VERSION 5.8 ;
BUSBITCHARS "[]" ;
DIVIDERCHAR "/" ;
 
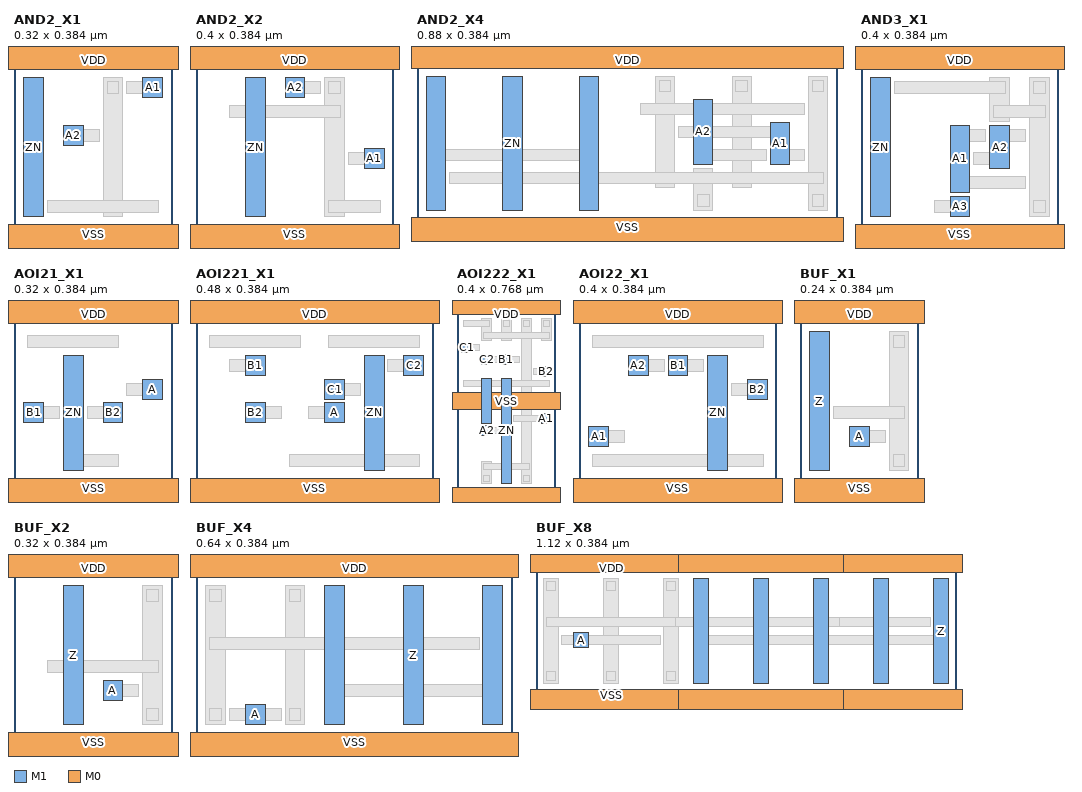
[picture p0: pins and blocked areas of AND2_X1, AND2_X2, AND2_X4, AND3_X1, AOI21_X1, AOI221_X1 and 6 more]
MACRO AND2_X1
  CLASS CORE ;
  FOREIGN AND2_X1 0 0 ;
  SIZE 0.32 BY 0.384 ;
  ORIGIN 0.0 0.0 ;
  SYMMETRY X Y ;
  PIN A1
    DIRECTION INPUT ;
    USE SIGNAL ;
    ANTENNAGATEAREA 0.00320 ;
    PORT
      LAYER M1 ;
        RECT 0.26 0.292 0.3 0.332 ;
    END
  END A1
  PIN A2
    DIRECTION INPUT ;
    USE SIGNAL ;
    ANTENNAGATEAREA 0.00320 ;
    PORT
      LAYER M1 ;
        RECT 0.1 0.196 0.14 0.236 ;
    END
  END A2
  PIN ZN
    DIRECTION OUTPUT ;
    USE SIGNAL ;
    ANTENNADIFFAREA 0.0096 ;
    PORT
      LAYER M1 ;
        RECT 0.02 0.052 0.06 0.332 ;
    END
  END ZN
  PIN VDD
    DIRECTION INOUT ;
    USE POWER ;
    PORT
      LAYER M0 ;
        RECT -0.02 0.348 0.34 0.42 ;
    END
  END VDD
  PIN VSS
    DIRECTION INOUT ;
    USE GROUND ;
    PORT
      LAYER M0 ;
        RECT -0.02 -0.036 0.34 0.036 ;
    END
  END VSS
  OBS
    LAYER M1 ;
      RECT 0.18 0.052 0.22 0.332 ;
    LAYER M0 ;
      RECT 0.068 0.06 0.292 0.084 ;
      RECT 0.188 0.3 0.212 0.324 ;
      RECT 0.228 0.3 0.292 0.324 ;
      RECT 0.108 0.204 0.172 0.228 ;
      RECT 0.028 0.06 0.052 0.084 ;
      RECT 0.028 0.3 0.052 0.324 ;
  END
END AND2_X1

MACRO AND2_X2
  CLASS CORE ;
  FOREIGN AND2_X2 0 0 ;
  SIZE 0.4 BY 0.384 ;
  ORIGIN 0.0 0.0 ;
  SYMMETRY X Y ;
  PIN A1
    DIRECTION INPUT ;
    USE SIGNAL ;
    ANTENNAGATEAREA 0.00320 ;
    PORT
      LAYER M1 ;
        RECT 0.34 0.148 0.38 0.188 ;
    END
  END A1
  PIN A2
    DIRECTION INPUT ;
    USE SIGNAL ;
    ANTENNAGATEAREA 0.00320 ;
    PORT
      LAYER M1 ;
        RECT 0.18 0.292 0.22 0.332 ;
    END
  END A2
  PIN ZN
    DIRECTION OUTPUT ;
    USE SIGNAL ;
    ANTENNADIFFAREA 0.0096 ;
    PORT
      LAYER M1 ;
        RECT 0.1 0.052 0.14 0.332 ;
    END
  END ZN
  PIN VDD
    DIRECTION INOUT ;
    USE POWER ;
    PORT
      LAYER M0 ;
        RECT -0.02 0.348 0.42 0.42 ;
    END
  END VDD
  PIN VSS
    DIRECTION INOUT ;
    USE GROUND ;
    PORT
      LAYER M0 ;
        RECT -0.02 -0.036 0.42 0.036 ;
    END
  END VSS
  OBS
    LAYER M1 ;
      RECT 0.26 0.052 0.3 0.332 ;
    LAYER M0 ;
      RECT 0.068 0.252 0.292 0.276 ;
      RECT 0.268 0.06 0.372 0.084 ;
      RECT 0.268 0.3 0.292 0.324 ;
      RECT 0.308 0.156 0.372 0.18 ;
      RECT 0.188 0.3 0.252 0.324 ;
      RECT 0.108 0.06 0.132 0.084 ;
      RECT 0.108 0.3 0.132 0.324 ;
  END
END AND2_X2

MACRO AND2_X4
  CLASS CORE ;
  FOREIGN AND2_X4 0 0 ;
  SIZE 0.88 BY 0.384 ;
  ORIGIN 0.0 0.0 ;
  SYMMETRY X Y ;
  PIN A1
    DIRECTION INPUT ;
    USE SIGNAL ;
    ANTENNAGATEAREA 0.00640 ;
    PORT
      LAYER M1 ;
        RECT 0.74 0.148 0.78 0.236 ;
    END
  END A1
  PIN A2
    DIRECTION INPUT ;
    USE SIGNAL ;
    ANTENNAGATEAREA 0.00640 ;
    PORT
      LAYER M1 ;
        RECT 0.58 0.148 0.62 0.284 ;
    END
  END A2
  PIN ZN
    DIRECTION OUTPUT ;
    USE SIGNAL ;
    ANTENNADIFFAREA 0.0288 ;
    PORT
      LAYER M1 ;
        RECT 0.02 0.052 0.06 0.332 ;
        RECT 0.18 0.052 0.22 0.332 ;
        RECT 0.34 0.052 0.38 0.332 ;
    END
  END ZN
  PIN VDD
    DIRECTION INOUT ;
    USE POWER ;
    PORT
      LAYER M0 ;
        RECT -0.02 0.348 0.9 0.42 ;
    END
  END VDD
  PIN VSS
    DIRECTION INOUT ;
    USE GROUND ;
    PORT
      LAYER M0 ;
        RECT -0.02 -0.036 0.9 0.036 ;
    END
  END VSS
  OBS
    LAYER M1 ;
      RECT 0.5 0.1 0.54 0.332 ;
      RECT 0.58 0.052 0.62 0.14 ;
      RECT 0.66 0.1 0.7 0.332 ;
      RECT 0.82 0.052 0.86 0.332 ;
    LAYER M0 ;
      RECT 0.068 0.108 0.852 0.132 ;
      RECT 0.508 0.3 0.532 0.324 ;
      RECT 0.668 0.3 0.692 0.324 ;
      RECT 0.828 0.3 0.852 0.324 ;
      RECT 0.588 0.06 0.612 0.084 ;
      RECT 0.828 0.06 0.852 0.084 ;
      RECT 0.748 0.156 0.812 0.18 ;
      RECT 0.548 0.204 0.772 0.228 ;
      RECT 0.588 0.156 0.732 0.18 ;
      RECT 0.468 0.252 0.812 0.276 ;
      RECT 0.028 0.06 0.052 0.084 ;
      RECT 0.028 0.156 0.372 0.18 ;
      RECT 0.028 0.3 0.052 0.324 ;
      RECT 0.188 0.06 0.212 0.084 ;
      RECT 0.188 0.3 0.212 0.324 ;
      RECT 0.348 0.3 0.372 0.324 ;
      RECT 0.348 0.06 0.372 0.084 ;
  END
END AND2_X4

MACRO AND3_X1
  CLASS CORE ;
  FOREIGN AND3_X1 0 0 ;
  SIZE 0.4 BY 0.384 ;
  ORIGIN 0.0 0.0 ;
  SYMMETRY X Y ;
  PIN A1
    DIRECTION INPUT ;
    USE SIGNAL ;
    ANTENNAGATEAREA 0.00320 ;
    PORT
      LAYER M1 ;
        RECT 0.18 0.1 0.22 0.236 ;
    END
  END A1
  PIN A2
    DIRECTION INPUT ;
    USE SIGNAL ;
    ANTENNAGATEAREA 0.00320 ;
    PORT
      LAYER M1 ;
        RECT 0.26 0.148 0.3 0.236 ;
    END
  END A2
  PIN A3
    DIRECTION INPUT ;
    USE SIGNAL ;
    ANTENNAGATEAREA 0.00320 ;
    PORT
      LAYER M1 ;
        RECT 0.18 0.052 0.22 0.092 ;
    END
  END A3
  PIN ZN
    DIRECTION OUTPUT ;
    USE SIGNAL ;
    ANTENNADIFFAREA 0.0096 ;
    PORT
      LAYER M1 ;
        RECT 0.02 0.052 0.06 0.332 ;
    END
  END ZN
  PIN VDD
    DIRECTION INOUT ;
    USE POWER ;
    PORT
      LAYER M0 ;
        RECT -0.02 0.348 0.42 0.42 ;
    END
  END VDD
  PIN VSS
    DIRECTION INOUT ;
    USE GROUND ;
    PORT
      LAYER M0 ;
        RECT -0.02 -0.036 0.42 0.036 ;
    END
  END VSS
  OBS
    LAYER M1 ;
      RECT 0.26 0.244 0.3 0.332 ;
      RECT 0.34 0.052 0.38 0.332 ;
    LAYER M0 ;
      RECT 0.068 0.3 0.292 0.324 ;
      RECT 0.268 0.252 0.372 0.276 ;
      RECT 0.348 0.3 0.372 0.324 ;
      RECT 0.348 0.06 0.372 0.084 ;
      RECT 0.188 0.108 0.332 0.132 ;
      RECT 0.188 0.204 0.252 0.228 ;
      RECT 0.268 0.204 0.332 0.228 ;
      RECT 0.228 0.156 0.292 0.18 ;
      RECT 0.148 0.06 0.212 0.084 ;
      RECT 0.028 0.06 0.052 0.084 ;
      RECT 0.028 0.3 0.052 0.324 ;
  END
END AND3_X1

MACRO AOI21_X1
  CLASS CORE ;
  FOREIGN AOI21_X1 0 0 ;
  SIZE 0.32 BY 0.384 ;
  ORIGIN 0.0 0.0 ;
  SYMMETRY X Y ;
  PIN A
    DIRECTION INPUT ;
    USE SIGNAL ;
    ANTENNAGATEAREA 0.00320 ;
    PORT
      LAYER M1 ;
        RECT 0.26 0.196 0.3 0.236 ;
    END
  END A
  PIN B1
    DIRECTION INPUT ;
    USE SIGNAL ;
    ANTENNAGATEAREA 0.00320 ;
    PORT
      LAYER M1 ;
        RECT 0.02 0.148 0.06 0.188 ;
    END
  END B1
  PIN B2
    DIRECTION INPUT ;
    USE SIGNAL ;
    ANTENNAGATEAREA 0.00320 ;
    PORT
      LAYER M1 ;
        RECT 0.18 0.148 0.22 0.188 ;
    END
  END B2
  PIN ZN
    DIRECTION OUTPUT ;
    USE SIGNAL ;
    ANTENNADIFFAREA 0.0096 ;
    PORT
      LAYER M1 ;
        RECT 0.1 0.052 0.14 0.284 ;
    END
  END ZN
  PIN VDD
    DIRECTION INOUT ;
    USE POWER ;
    PORT
      LAYER M0 ;
        RECT -0.02 0.348 0.34 0.42 ;
    END
  END VDD
  PIN VSS
    DIRECTION INOUT ;
    USE GROUND ;
    PORT
      LAYER M0 ;
        RECT -0.02 -0.036 0.34 0.036 ;
    END
  END VSS
  OBS
    LAYER M0 ;
      RECT 0.028 0.3 0.212 0.324 ;
      RECT 0.228 0.204 0.292 0.228 ;
      RECT 0.028 0.156 0.092 0.18 ;
      RECT 0.148 0.156 0.212 0.18 ;
      RECT 0.108 0.06 0.212 0.084 ;
      RECT 0.108 0.252 0.132 0.276 ;
  END
END AOI21_X1

MACRO AOI221_X1
  CLASS CORE ;
  FOREIGN AOI221_X1 0 0 ;
  SIZE 0.48 BY 0.384 ;
  ORIGIN 0.0 0.0 ;
  SYMMETRY X Y ;
  PIN A
    DIRECTION INPUT ;
    USE SIGNAL ;
    ANTENNAGATEAREA 0.00320 ;
    PORT
      LAYER M1 ;
        RECT 0.26 0.148 0.3 0.188 ;
    END
  END A
  PIN B1
    DIRECTION INPUT ;
    USE SIGNAL ;
    ANTENNAGATEAREA 0.00320 ;
    PORT
      LAYER M1 ;
        RECT 0.1 0.244 0.14 0.284 ;
    END
  END B1
  PIN B2
    DIRECTION INPUT ;
    USE SIGNAL ;
    ANTENNAGATEAREA 0.00320 ;
    PORT
      LAYER M1 ;
        RECT 0.1 0.148 0.14 0.188 ;
    END
  END B2
  PIN C1
    DIRECTION INPUT ;
    USE SIGNAL ;
    ANTENNAGATEAREA 0.00320 ;
    PORT
      LAYER M1 ;
        RECT 0.26 0.196 0.3 0.236 ;
    END
  END C1
  PIN C2
    DIRECTION INPUT ;
    USE SIGNAL ;
    ANTENNAGATEAREA 0.00320 ;
    PORT
      LAYER M1 ;
        RECT 0.42 0.244 0.46 0.284 ;
    END
  END C2
  PIN ZN
    DIRECTION OUTPUT ;
    USE SIGNAL ;
    ANTENNADIFFAREA 0.0144 ;
    PORT
      LAYER M1 ;
        RECT 0.34 0.052 0.38 0.284 ;
    END
  END ZN
  PIN VDD
    DIRECTION INOUT ;
    USE POWER ;
    PORT
      LAYER M0 ;
        RECT -0.02 0.348 0.5 0.42 ;
    END
  END VDD
  PIN VSS
    DIRECTION INOUT ;
    USE GROUND ;
    PORT
      LAYER M0 ;
        RECT -0.02 -0.036 0.5 0.036 ;
    END
  END VSS
  OBS
    LAYER M0 ;
      RECT 0.268 0.3 0.452 0.324 ;
      RECT 0.028 0.3 0.212 0.324 ;
      RECT 0.228 0.156 0.292 0.18 ;
      RECT 0.068 0.252 0.132 0.276 ;
      RECT 0.108 0.156 0.172 0.18 ;
      RECT 0.268 0.204 0.332 0.228 ;
      RECT 0.388 0.252 0.452 0.276 ;
      RECT 0.188 0.06 0.452 0.084 ;
      RECT 0.348 0.252 0.372 0.276 ;
  END
END AOI221_X1

MACRO AOI222_X1
  CLASS CORE ;
  FOREIGN AOI222_X1 0 0 ;
  SIZE 0.4 BY 0.768 ;
  ORIGIN 0.0 0.0 ;
  SYMMETRY X Y ;
  PIN A1
    DIRECTION INPUT ;
    USE SIGNAL ;
    ANTENNAGATEAREA 0.00320 ;
    PORT
      LAYER M1 ;
        RECT 0.34 0.292 0.38 0.332 ;
    END
  END A1
  PIN A2
    DIRECTION INPUT ;
    USE SIGNAL ;
    ANTENNAGATEAREA 0.00320 ;
    PORT
      LAYER M1 ;
        RECT 0.1 0.244 0.14 0.284 ;
    END
  END A2
  PIN B1
    DIRECTION INPUT ;
    USE SIGNAL ;
    ANTENNAGATEAREA 0.00320 ;
    PORT
      LAYER M1 ;
        RECT 0.18 0.532 0.22 0.572 ;
    END
  END B1
  PIN B2
    DIRECTION INPUT ;
    USE SIGNAL ;
    ANTENNAGATEAREA 0.00320 ;
    PORT
      LAYER M1 ;
        RECT 0.34 0.484 0.38 0.524 ;
    END
  END B2
  PIN C1
    DIRECTION INPUT ;
    USE SIGNAL ;
    ANTENNAGATEAREA 0.00320 ;
    PORT
      LAYER M1 ;
        RECT 0.02 0.58 0.06 0.62 ;
    END
  END C1
  PIN C2
    DIRECTION INPUT ;
    USE SIGNAL ;
    ANTENNAGATEAREA 0.00320 ;
    PORT
      LAYER M1 ;
        RECT 0.1 0.532 0.14 0.572 ;
    END
  END C2
  PIN ZN
    DIRECTION OUTPUT ;
    USE SIGNAL ;
    ANTENNADIFFAREA 0.0192 ;
    PORT
      LAYER M1 ;
        RECT 0.1 0.292 0.14 0.476 ;
        RECT 0.18 0.052 0.22 0.476 ;
    END
  END ZN
  PIN VDD
    DIRECTION INOUT ;
    USE POWER ;
    PORT
      LAYER M0 ;
        RECT -0.02 -0.036 0.42 0.036 ;
        RECT -0.02 0.732 0.42 0.804 ;
    END
  END VDD
  PIN VSS
    DIRECTION INOUT ;
    USE GROUND ;
    PORT
      LAYER M0 ;
        RECT -0.02 0.348 0.42 0.42 ;
    END
  END VSS
  OBS
    LAYER M1 ;
      RECT 0.34 0.628 0.38 0.716 ;
      RECT 0.18 0.628 0.22 0.716 ;
      RECT 0.1 0.628 0.14 0.716 ;
      RECT 0.26 0.052 0.3 0.716 ;
      RECT 0.1 0.052 0.14 0.14 ;
    LAYER M0 ;
      RECT 0.348 0.684 0.372 0.708 ;
      RECT 0.188 0.684 0.212 0.708 ;
      RECT 0.268 0.06 0.292 0.084 ;
      RECT 0.108 0.06 0.132 0.084 ;
      RECT 0.268 0.684 0.292 0.708 ;
      RECT 0.108 0.636 0.372 0.66 ;
      RECT 0.028 0.684 0.132 0.708 ;
      RECT 0.108 0.108 0.292 0.132 ;
      RECT 0.228 0.3 0.372 0.324 ;
      RECT 0.108 0.252 0.172 0.276 ;
      RECT 0.188 0.54 0.252 0.564 ;
      RECT 0.308 0.492 0.372 0.516 ;
      RECT 0.028 0.588 0.092 0.612 ;
      RECT 0.108 0.54 0.172 0.564 ;
      RECT 0.028 0.444 0.372 0.468 ;
      RECT 0.108 0.3 0.132 0.324 ;
      RECT 0.188 0.06 0.212 0.084 ;
  END
END AOI222_X1

MACRO AOI22_X1
  CLASS CORE ;
  FOREIGN AOI22_X1 0 0 ;
  SIZE 0.4 BY 0.384 ;
  ORIGIN 0.0 0.0 ;
  SYMMETRY X Y ;
  PIN A1
    DIRECTION INPUT ;
    USE SIGNAL ;
    ANTENNAGATEAREA 0.00320 ;
    PORT
      LAYER M1 ;
        RECT 0.02 0.1 0.06 0.14 ;
    END
  END A1
  PIN A2
    DIRECTION INPUT ;
    USE SIGNAL ;
    ANTENNAGATEAREA 0.00320 ;
    PORT
      LAYER M1 ;
        RECT 0.1 0.244 0.14 0.284 ;
    END
  END A2
  PIN B1
    DIRECTION INPUT ;
    USE SIGNAL ;
    ANTENNAGATEAREA 0.00320 ;
    PORT
      LAYER M1 ;
        RECT 0.18 0.244 0.22 0.284 ;
    END
  END B1
  PIN B2
    DIRECTION INPUT ;
    USE SIGNAL ;
    ANTENNAGATEAREA 0.00320 ;
    PORT
      LAYER M1 ;
        RECT 0.34 0.196 0.38 0.236 ;
    END
  END B2
  PIN ZN
    DIRECTION OUTPUT ;
    USE SIGNAL ;
    ANTENNADIFFAREA 0.0144 ;
    PORT
      LAYER M1 ;
        RECT 0.26 0.052 0.3 0.284 ;
    END
  END ZN
  PIN VDD
    DIRECTION INOUT ;
    USE POWER ;
    PORT
      LAYER M0 ;
        RECT -0.02 0.348 0.42 0.42 ;
    END
  END VDD
  PIN VSS
    DIRECTION INOUT ;
    USE GROUND ;
    PORT
      LAYER M0 ;
        RECT -0.02 -0.036 0.42 0.036 ;
    END
  END VSS
  OBS
    LAYER M0 ;
      RECT 0.028 0.3 0.372 0.324 ;
      RECT 0.028 0.108 0.092 0.132 ;
      RECT 0.108 0.252 0.172 0.276 ;
      RECT 0.188 0.252 0.252 0.276 ;
      RECT 0.308 0.204 0.372 0.228 ;
      RECT 0.028 0.06 0.372 0.084 ;
      RECT 0.268 0.252 0.292 0.276 ;
  END
END AOI22_X1

MACRO BUF_X1
  CLASS CORE ;
  FOREIGN BUF_X1 0 0 ;
  SIZE 0.24 BY 0.384 ;
  ORIGIN 0.0 0.0 ;
  SYMMETRY X Y ;
  PIN A
    DIRECTION INPUT ;
    USE SIGNAL ;
    ANTENNAGATEAREA 0.00320 ;
    PORT
      LAYER M1 ;
        RECT 0.1 0.1 0.14 0.14 ;
    END
  END A
  PIN Z
    DIRECTION OUTPUT ;
    USE SIGNAL ;
    ANTENNADIFFAREA 0.0096 ;
    PORT
      LAYER M1 ;
        RECT 0.02 0.052 0.06 0.332 ;
    END
  END Z
  PIN VDD
    DIRECTION INOUT ;
    USE POWER ;
    PORT
      LAYER M0 ;
        RECT -0.02 0.348 0.26 0.42 ;
    END
  END VDD
  PIN VSS
    DIRECTION INOUT ;
    USE GROUND ;
    PORT
      LAYER M0 ;
        RECT -0.02 -0.036 0.26 0.036 ;
    END
  END VSS
  OBS
    LAYER M1 ;
      RECT 0.18 0.052 0.22 0.332 ;
    LAYER M0 ;
      RECT 0.068 0.156 0.212 0.18 ;
      RECT 0.188 0.3 0.212 0.324 ;
      RECT 0.188 0.06 0.212 0.084 ;
      RECT 0.108 0.108 0.172 0.132 ;
      RECT 0.028 0.06 0.052 0.084 ;
      RECT 0.028 0.3 0.052 0.324 ;
  END
END BUF_X1

MACRO BUF_X2
  CLASS CORE ;
  FOREIGN BUF_X2 0 0 ;
  SIZE 0.32 BY 0.384 ;
  ORIGIN 0.0 0.0 ;
  SYMMETRY X Y ;
  PIN A
    DIRECTION INPUT ;
    USE SIGNAL ;
    ANTENNAGATEAREA 0.00320 ;
    PORT
      LAYER M1 ;
        RECT 0.18 0.1 0.22 0.14 ;
    END
  END A
  PIN Z
    DIRECTION OUTPUT ;
    USE SIGNAL ;
    ANTENNADIFFAREA 0.0096 ;
    PORT
      LAYER M1 ;
        RECT 0.1 0.052 0.14 0.332 ;
    END
  END Z
  PIN VDD
    DIRECTION INOUT ;
    USE POWER ;
    PORT
      LAYER M0 ;
        RECT -0.02 0.348 0.34 0.42 ;
    END
  END VDD
  PIN VSS
    DIRECTION INOUT ;
    USE GROUND ;
    PORT
      LAYER M0 ;
        RECT -0.02 -0.036 0.34 0.036 ;
    END
  END VSS
  OBS
    LAYER M1 ;
      RECT 0.26 0.052 0.3 0.332 ;
    LAYER M0 ;
      RECT 0.068 0.156 0.292 0.18 ;
      RECT 0.268 0.3 0.292 0.324 ;
      RECT 0.268 0.06 0.292 0.084 ;
      RECT 0.188 0.108 0.252 0.132 ;
      RECT 0.108 0.06 0.132 0.084 ;
      RECT 0.108 0.3 0.132 0.324 ;
  END
END BUF_X2

MACRO BUF_X4
  CLASS CORE ;
  FOREIGN BUF_X4 0 0 ;
  SIZE 0.64 BY 0.384 ;
  ORIGIN 0.0 0.0 ;
  SYMMETRY X Y ;
  PIN A
    DIRECTION INPUT ;
    USE SIGNAL ;
    ANTENNAGATEAREA 0.00640 ;
    PORT
      LAYER M1 ;
        RECT 0.1 0.052 0.14 0.092 ;
    END
  END A
  PIN Z
    DIRECTION OUTPUT ;
    USE SIGNAL ;
    ANTENNADIFFAREA 0.0288 ;
    PORT
      LAYER M1 ;
        RECT 0.26 0.052 0.3 0.332 ;
        RECT 0.42 0.052 0.46 0.332 ;
        RECT 0.58 0.052 0.62 0.332 ;
    END
  END Z
  PIN VDD
    DIRECTION INOUT ;
    USE POWER ;
    PORT
      LAYER M0 ;
        RECT -0.02 0.348 0.66 0.42 ;
    END
  END VDD
  PIN VSS
    DIRECTION INOUT ;
    USE GROUND ;
    PORT
      LAYER M0 ;
        RECT -0.02 -0.036 0.66 0.036 ;
    END
  END VSS
  OBS
    LAYER M1 ;
      RECT 0.02 0.052 0.06 0.332 ;
      RECT 0.18 0.052 0.22 0.332 ;
    LAYER M0 ;
      RECT 0.028 0.204 0.572 0.228 ;
      RECT 0.028 0.3 0.052 0.324 ;
      RECT 0.188 0.3 0.212 0.324 ;
      RECT 0.028 0.06 0.052 0.084 ;
      RECT 0.188 0.06 0.212 0.084 ;
      RECT 0.068 0.06 0.172 0.084 ;
      RECT 0.268 0.06 0.292 0.084 ;
      RECT 0.268 0.3 0.292 0.324 ;
      RECT 0.268 0.108 0.612 0.132 ;
      RECT 0.588 0.06 0.612 0.084 ;
      RECT 0.428 0.06 0.452 0.084 ;
      RECT 0.588 0.3 0.612 0.324 ;
      RECT 0.428 0.3 0.452 0.324 ;
  END
END BUF_X4

MACRO BUF_X8
  CLASS CORE ;
  FOREIGN BUF_X8 0 0 ;
  SIZE 1.12 BY 0.384 ;
  ORIGIN 0.0 0.0 ;
  SYMMETRY X Y ;
  PIN A
    DIRECTION INPUT ;
    USE SIGNAL ;
    ANTENNAGATEAREA 0.01280 ;
    PORT
      LAYER M1 ;
        RECT 0.1 0.148 0.14 0.188 ;
    END
  END A
  PIN Z
    DIRECTION OUTPUT ;
    USE SIGNAL ;
    ANTENNADIFFAREA 0.0480 ;
    PORT
      LAYER M1 ;
        RECT 1.06 0.052 1.1 0.332 ;
        RECT 0.74 0.052 0.78 0.332 ;
        RECT 0.42 0.052 0.46 0.332 ;
        RECT 0.58 0.052 0.62 0.332 ;
        RECT 0.9 0.052 0.94 0.332 ;
    END
  END Z
  PIN VDD
    DIRECTION INOUT ;
    USE POWER ;
    PORT
      LAYER M0 ;
        RECT 0.7 0.348 1.14 0.42 ;
        RECT -0.02 0.348 0.42 0.42 ;
        RECT 0.38 0.348 0.82 0.42 ;
    END
  END VDD
  PIN VSS
    DIRECTION INOUT ;
    USE GROUND ;
    PORT
      LAYER M0 ;
        RECT 0.7 -0.036 1.14 0.036 ;
        RECT 0.38 -0.036 0.82 0.036 ;
        RECT -0.02 -0.036 0.42 0.036 ;
    END
  END VSS
  OBS
    LAYER M1 ;
      RECT 0.34 0.052 0.38 0.332 ;
      RECT 0.18 0.052 0.22 0.332 ;
      RECT 0.02 0.052 0.06 0.332 ;
    LAYER M0 ;
      RECT 0.788 0.204 1.052 0.228 ;
      RECT 0.34 0.204 0.81 0.228 ;
      RECT 0.348 0.06 0.372 0.084 ;
      RECT 0.188 0.06 0.212 0.084 ;
      RECT 0.028 0.06 0.052 0.084 ;
      RECT 0.348 0.3 0.372 0.324 ;
      RECT 0.188 0.3 0.212 0.324 ;
      RECT 0.028 0.3 0.052 0.324 ;
      RECT 0.028 0.204 0.372 0.228 ;
      RECT 0.068 0.156 0.332 0.18 ;
      RECT 0.748 0.156 1.092 0.18 ;
      RECT 1.068 0.06 1.092 0.084 ;
      RECT 1.068 0.3 1.092 0.324 ;
      RECT 0.428 0.156 0.772 0.18 ;
      RECT 0.748 0.06 0.772 0.084 ;
      RECT 0.748 0.3 0.772 0.324 ;
      RECT 0.908 0.3 0.932 0.324 ;
      RECT 0.588 0.3 0.612 0.324 ;
      RECT 0.908 0.06 0.932 0.084 ;
      RECT 0.428 0.06 0.452 0.084 ;
      RECT 0.588 0.06 0.612 0.084 ;
      RECT 0.428 0.3 0.452 0.324 ;
  END
END BUF_X8

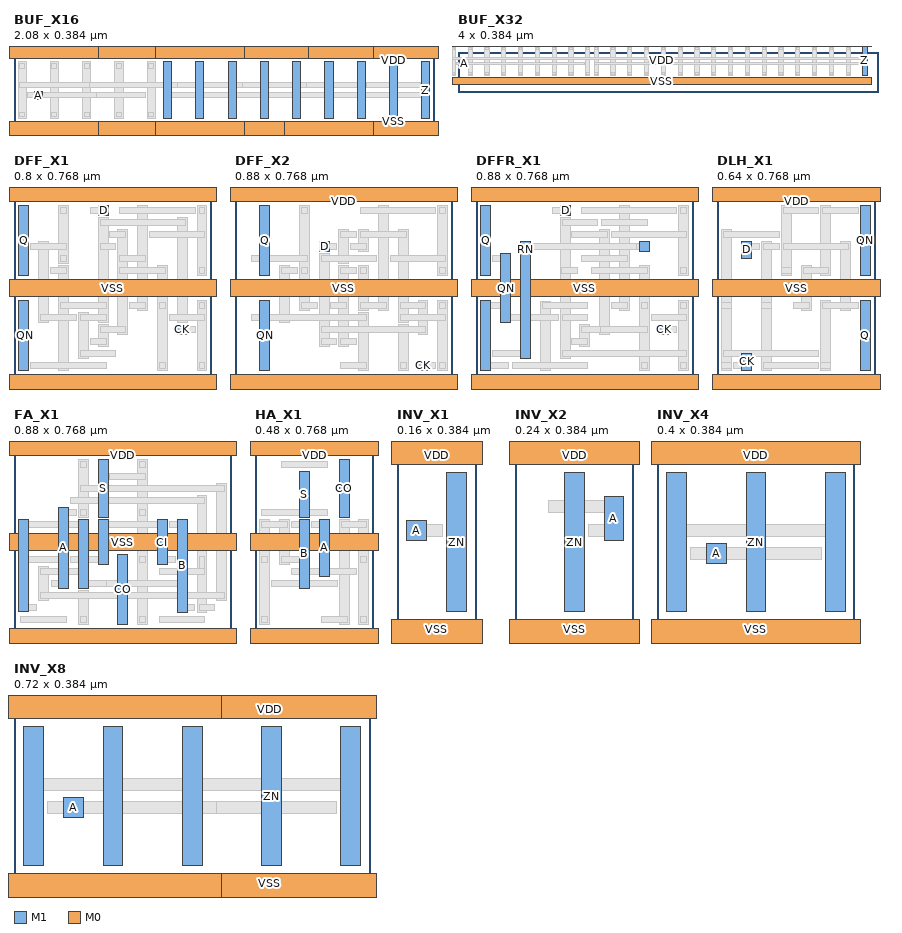
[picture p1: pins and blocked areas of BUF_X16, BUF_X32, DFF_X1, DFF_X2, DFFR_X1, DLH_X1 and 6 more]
MACRO BUF_X16
  CLASS CORE ;
  FOREIGN BUF_X16 0 0 ;
  SIZE 2.08 BY 0.384 ;
  ORIGIN 0.0 0.0 ;
  SYMMETRY X Y ;
  PIN A
    DIRECTION INPUT ;
    USE SIGNAL ;
    ANTENNAGATEAREA 0.02560 ;
    PORT
      LAYER M1 ;
        RECT 0.1 0.148 0.14 0.188 ;
    END
  END A
  PIN Z
    DIRECTION OUTPUT ;
    USE SIGNAL ;
    ANTENNADIFFAREA 0.0864 ;
    PORT
      LAYER M1 ;
        RECT 2.02 0.052 2.06 0.332 ;
        RECT 1.7 0.052 1.74 0.332 ;
        RECT 1.86 0.052 1.9 0.332 ;
        RECT 1.22 0.052 1.26 0.332 ;
        RECT 0.9 0.052 0.94 0.332 ;
        RECT 1.06 0.052 1.1 0.332 ;
        RECT 0.74 0.052 0.78 0.332 ;
        RECT 1.38 0.052 1.42 0.332 ;
        RECT 1.54 0.052 1.58 0.332 ;
    END
  END Z
  PIN VDD
    DIRECTION INOUT ;
    USE POWER ;
    PORT
      LAYER M0 ;
        RECT 1.34 0.348 1.78 0.42 ;
        RECT 1.66 0.348 2.1 0.42 ;
        RECT 1.02 0.348 1.46 0.42 ;
        RECT 0.3 0.348 0.74 0.42 ;
        RECT 0.7 0.348 1.14 0.42 ;
        RECT -0.02 0.348 0.42 0.42 ;
        RECT 1.34 0.348 1.78 0.42 ;
        RECT 1.02 0.348 1.46 0.42 ;
        RECT 1.66 0.348 2.1 0.42 ;
        RECT 0.3 0.348 0.74 0.42 ;
        RECT 0.7 0.348 1.14 0.42 ;
        RECT -0.02 0.348 0.42 0.42 ;
    END
  END VDD
  PIN VSS
    DIRECTION INOUT ;
    USE GROUND ;
    PORT
      LAYER M0 ;
        RECT 1.02 -0.036 1.46 0.036 ;
        RECT 1.34 -0.036 1.78 0.036 ;
        RECT 1.66 -0.036 2.1 0.036 ;
        RECT 0.3 -0.036 0.74 0.036 ;
        RECT -0.02 -0.036 0.42 0.036 ;
        RECT 0.7 -0.036 1.14 0.036 ;
        RECT 1.02 -0.036 1.46 0.036 ;
        RECT 1.34 -0.036 1.78 0.036 ;
        RECT 1.66 -0.036 2.1 0.036 ;
        RECT 0.3 -0.036 0.74 0.036 ;
        RECT -0.02 -0.036 0.42 0.036 ;
        RECT 0.7 -0.036 1.14 0.036 ;
    END
  END VSS
  OBS
    LAYER M1 ;
      RECT 0.66 0.052 0.7 0.332 ;
      RECT 0.5 0.052 0.54 0.332 ;
      RECT 0.34 0.052 0.38 0.332 ;
      RECT 0.18 0.052 0.22 0.332 ;
      RECT 0.02 0.052 0.06 0.332 ;
    LAYER M0 ;
      RECT 1.428 0.204 1.77 0.228 ;
      RECT 1.748 0.204 2.012 0.228 ;
      RECT 1.108 0.204 1.45 0.228 ;
      RECT 0.788 0.204 1.13 0.228 ;
      RECT 0.668 0.06 0.692 0.084 ;
      RECT 0.508 0.06 0.532 0.084 ;
      RECT 0.348 0.06 0.372 0.084 ;
      RECT 0.668 0.3 0.692 0.324 ;
      RECT 0.508 0.3 0.532 0.324 ;
      RECT 0.348 0.3 0.372 0.324 ;
      RECT 0.348 0.204 0.81 0.228 ;
      RECT 0.188 0.06 0.212 0.084 ;
      RECT 0.028 0.06 0.052 0.084 ;
      RECT 0.188 0.3 0.212 0.324 ;
      RECT 0.028 0.3 0.052 0.324 ;
      RECT 0.028 0.204 0.372 0.228 ;
      RECT 0.388 0.156 0.652 0.18 ;
      RECT 0.068 0.156 0.41 0.18 ;
      RECT 0.748 0.156 1.092 0.18 ;
      RECT 2.028 0.06 2.052 0.084 ;
      RECT 1.708 0.156 2.052 0.18 ;
      RECT 1.388 0.156 1.732 0.18 ;
      RECT 1.068 0.156 1.412 0.18 ;
      RECT 2.028 0.3 2.052 0.324 ;
      RECT 1.868 0.3 1.892 0.324 ;
      RECT 1.068 0.3 1.092 0.324 ;
      RECT 1.548 0.06 1.572 0.084 ;
      RECT 1.868 0.06 1.892 0.084 ;
      RECT 0.748 0.06 0.772 0.084 ;
      RECT 1.068 0.06 1.092 0.084 ;
      RECT 0.908 0.06 0.932 0.084 ;
      RECT 1.388 0.3 1.412 0.324 ;
      RECT 1.708 0.06 1.732 0.084 ;
      RECT 0.748 0.3 0.772 0.324 ;
      RECT 0.908 0.3 0.932 0.324 ;
      RECT 1.388 0.06 1.412 0.084 ;
      RECT 1.228 0.06 1.252 0.084 ;
      RECT 1.708 0.3 1.732 0.324 ;
      RECT 1.228 0.3 1.252 0.324 ;
      RECT 1.548 0.3 1.572 0.324 ;
  END
END BUF_X16

MACRO BUF_X32
  CLASS CORE ;
  ORIGIN 0 0 ;
  FOREIGN BUF_X32 0 0 ;
  SIZE 4 BY 0.384 ;
  PIN VDD
    DIRECTION INOUT ;
    USE POWER ;
    PORT
      LAYER M0 ;
        RECT -0.104 0.452 3.936 0.524 ;
    END
  END VDD
  PIN VSS
    DIRECTION INOUT ;
    USE GROUND ;
    PORT
      LAYER M0 ;
        RECT -0.104 0.068 3.936 0.14 ;
    END
  END VSS
  PIN A
    DIRECTION INOUT ;
    USE SIGNAL ;
    PORT
      LAYER M1 ;
        RECT 0.016 0.252 0.056 0.292 ;
    END
  END A
  PIN Z
    DIRECTION INOUT ;
    USE SIGNAL ;
    PORT
      LAYER M1 ;
        RECT 3.856 0.156 3.896 0.436 ;
    END
  END Z
  OBS
    LAYER M1 SPACING 0 ;
      RECT -0.064 0.156 -0.024 0.436 ;
      RECT 0.096 0.156 0.136 0.436 ;
      RECT 0.256 0.156 0.296 0.436 ;
      RECT 0.416 0.156 0.456 0.436 ;
      RECT 0.576 0.156 0.616 0.436 ;
      RECT 0.736 0.156 0.776 0.436 ;
      RECT 0.896 0.156 0.936 0.436 ;
      RECT 1.056 0.156 1.096 0.436 ;
      RECT 1.216 0.156 1.256 0.436 ;
      RECT 1.296 0.156 1.336 0.436 ;
      RECT 1.456 0.156 1.496 0.436 ;
      RECT 1.616 0.156 1.656 0.436 ;
      RECT 1.776 0.156 1.816 0.436 ;
      RECT 1.936 0.156 1.976 0.436 ;
      RECT 2.096 0.156 2.136 0.436 ;
      RECT 2.256 0.156 2.296 0.436 ;
      RECT 2.416 0.156 2.456 0.436 ;
      RECT 2.576 0.156 2.616 0.436 ;
      RECT 2.736 0.156 2.776 0.436 ;
      RECT 2.896 0.156 2.936 0.436 ;
      RECT 3.056 0.156 3.096 0.436 ;
      RECT 3.216 0.156 3.256 0.436 ;
      RECT 3.376 0.156 3.416 0.436 ;
      RECT 3.536 0.156 3.576 0.436 ;
      RECT 3.696 0.156 3.736 0.436 ;
    LAYER M0 SPACING 0 ;
      RECT -0.056 0.164 -0.032 0.188 ;
      RECT 0.104 0.164 0.128 0.188 ;
      RECT 0.264 0.164 0.288 0.188 ;
      RECT 0.424 0.164 0.448 0.188 ;
      RECT 0.584 0.164 0.608 0.188 ;
      RECT 0.744 0.164 0.768 0.188 ;
      RECT 0.904 0.164 0.928 0.188 ;
      RECT 1.064 0.164 1.088 0.188 ;
      RECT 1.224 0.164 1.248 0.188 ;
      RECT 1.304 0.164 1.328 0.188 ;
      RECT 1.464 0.164 1.488 0.188 ;
      RECT 1.624 0.164 1.648 0.188 ;
      RECT 1.784 0.164 1.808 0.188 ;
      RECT 1.944 0.164 1.968 0.188 ;
      RECT 2.104 0.164 2.128 0.188 ;
      RECT 2.264 0.164 2.288 0.188 ;
      RECT 2.424 0.164 2.448 0.188 ;
      RECT 2.584 0.164 2.608 0.188 ;
      RECT 2.744 0.164 2.768 0.188 ;
      RECT 2.904 0.164 2.928 0.188 ;
      RECT 3.064 0.164 3.088 0.188 ;
      RECT 3.224 0.164 3.248 0.188 ;
      RECT 3.384 0.164 3.408 0.188 ;
      RECT 3.544 0.164 3.568 0.188 ;
      RECT 3.704 0.164 3.728 0.188 ;
      RECT 3.864 0.164 3.888 0.188 ;
      RECT -0.016 0.26 1.208 0.284 ;
      RECT 1.304 0.26 3.888 0.284 ;
      RECT -0.056 0.308 3.848 0.332 ;
      RECT -0.056 0.404 -0.032 0.428 ;
      RECT 0.104 0.404 0.128 0.428 ;
      RECT 0.264 0.404 0.288 0.428 ;
      RECT 0.424 0.404 0.448 0.428 ;
      RECT 0.584 0.404 0.608 0.428 ;
      RECT 0.744 0.404 0.768 0.428 ;
      RECT 0.904 0.404 0.928 0.428 ;
      RECT 1.064 0.404 1.088 0.428 ;
      RECT 1.224 0.404 1.248 0.428 ;
      RECT 1.304 0.404 1.328 0.428 ;
      RECT 1.464 0.404 1.488 0.428 ;
      RECT 1.624 0.404 1.648 0.428 ;
      RECT 1.784 0.404 1.808 0.428 ;
      RECT 1.944 0.404 1.968 0.428 ;
      RECT 2.104 0.404 2.128 0.428 ;
      RECT 2.264 0.404 2.288 0.428 ;
      RECT 2.424 0.404 2.448 0.428 ;
      RECT 2.584 0.404 2.608 0.428 ;
      RECT 2.744 0.404 2.768 0.428 ;
      RECT 2.904 0.404 2.928 0.428 ;
      RECT 3.064 0.404 3.088 0.428 ;
      RECT 3.224 0.404 3.248 0.428 ;
      RECT 3.384 0.404 3.408 0.428 ;
      RECT 3.544 0.404 3.568 0.428 ;
      RECT 3.704 0.404 3.728 0.428 ;
      RECT 3.864 0.404 3.888 0.428 ;
  END
END BUF_X32


MACRO DFF_X1
  CLASS CORE ;
  FOREIGN DFF_X1 0 0 ;
  SIZE 0.8 BY 0.768 ;
  ORIGIN 0.0 0.0 ;
  SYMMETRY X Y ;
  PIN CK
    DIRECTION INPUT ;
    USE CLOCK ;
    ANTENNAGATEAREA 0.00320 ;
    PORT
      LAYER M1 ;
        RECT 0.66 0.196 0.7 0.236 ;
    END
  END CK
  PIN D
    DIRECTION INPUT ;
    USE SIGNAL ;
    ANTENNAGATEAREA 0.00320 ;
    PORT
      LAYER M1 ;
        RECT 0.34 0.676 0.38 0.716 ;
    END
  END D
  PIN Q
    DIRECTION OUTPUT ;
    USE SIGNAL ;
    ANTENNADIFFAREA 0.0096 ;
    PORT
      LAYER M1 ;
        RECT 0.02 0.436 0.06 0.716 ;
    END
  END Q
  PIN QN
    DIRECTION OUTPUT ;
    USE SIGNAL ;
    ANTENNADIFFAREA 0.0096 ;
    PORT
      LAYER M1 ;
        RECT 0.02 0.052 0.06 0.332 ;
    END
  END QN
  PIN VDD
    DIRECTION INOUT ;
    USE POWER ;
    PORT
      LAYER M0 ;
        RECT -0.02 0.732 0.82 0.804 ;
        RECT -0.02 -0.036 0.82 0.036 ;
    END
  END VDD
  PIN VSS
    DIRECTION INOUT ;
    USE GROUND ;
    PORT
      LAYER M0 ;
        RECT -0.02 0.348 0.82 0.42 ;
    END
  END VSS
  OBS
    LAYER M1 ;
      RECT 0.34 0.148 0.38 0.236 ;
      RECT 0.42 0.196 0.46 0.62 ;
      RECT 0.58 0.052 0.62 0.476 ;
      RECT 0.74 0.436 0.78 0.716 ;
      RECT 0.5 0.292 0.54 0.716 ;
      RECT 0.26 0.1 0.3 0.284 ;
      RECT 0.34 0.244 0.38 0.668 ;
      RECT 0.66 0.244 0.7 0.668 ;
      RECT 0.74 0.052 0.78 0.332 ;
      RECT 0.18 0.052 0.22 0.476 ;
      RECT 0.1 0.244 0.14 0.572 ;
      RECT 0.18 0.484 0.22 0.716 ;
    LAYER M0 ;
      RECT 0.388 0.588 0.452 0.612 ;
      RECT 0.428 0.444 0.612 0.468 ;
      RECT 0.348 0.204 0.452 0.228 ;
      RECT 0.308 0.156 0.372 0.18 ;
      RECT 0.548 0.588 0.772 0.612 ;
      RECT 0.428 0.684 0.732 0.708 ;
      RECT 0.428 0.492 0.532 0.516 ;
      RECT 0.468 0.3 0.532 0.324 ;
      RECT 0.348 0.636 0.692 0.66 ;
      RECT 0.348 0.54 0.412 0.564 ;
      RECT 0.268 0.252 0.372 0.276 ;
      RECT 0.628 0.252 0.772 0.276 ;
      RECT 0.268 0.108 0.412 0.132 ;
      RECT 0.148 0.444 0.212 0.468 ;
      RECT 0.188 0.3 0.372 0.324 ;
      RECT 0.068 0.06 0.372 0.084 ;
      RECT 0.068 0.54 0.212 0.564 ;
      RECT 0.108 0.252 0.252 0.276 ;
      RECT 0.588 0.3 0.612 0.324 ;
      RECT 0.588 0.06 0.612 0.084 ;
      RECT 0.748 0.684 0.772 0.708 ;
      RECT 0.748 0.444 0.772 0.468 ;
      RECT 0.748 0.3 0.772 0.324 ;
      RECT 0.748 0.06 0.772 0.084 ;
      RECT 0.188 0.684 0.212 0.708 ;
      RECT 0.188 0.492 0.212 0.516 ;
      RECT 0.668 0.204 0.732 0.228 ;
      RECT 0.308 0.684 0.372 0.708 ;
      RECT 0.028 0.444 0.052 0.468 ;
      RECT 0.028 0.684 0.052 0.708 ;
      RECT 0.028 0.06 0.052 0.084 ;
      RECT 0.028 0.3 0.052 0.324 ;
  END
END DFF_X1

MACRO DFF_X2
  CLASS CORE ;
  FOREIGN DFF_X2 0 0 ;
  SIZE 0.88 BY 0.768 ;
  ORIGIN 0.0 0.0 ;
  SYMMETRY X Y ;
  PIN CK
    DIRECTION INPUT ;
    USE CLOCK ;
    ANTENNAGATEAREA 0.00320 ;
    PORT
      LAYER M1 ;
        RECT 0.74 0.052 0.78 0.092 ;
    END
  END CK
  PIN D
    DIRECTION INPUT ;
    USE SIGNAL ;
    ANTENNAGATEAREA 0.00320 ;
    PORT
      LAYER M1 ;
        RECT 0.34 0.532 0.38 0.572 ;
    END
  END D
  PIN Q
    DIRECTION OUTPUT ;
    USE SIGNAL ;
    ANTENNADIFFAREA 0.0096 ;
    PORT
      LAYER M1 ;
        RECT 0.1 0.436 0.14 0.716 ;
    END
  END Q
  PIN QN
    DIRECTION OUTPUT ;
    USE SIGNAL ;
    ANTENNADIFFAREA 0.0096 ;
    PORT
      LAYER M1 ;
        RECT 0.1 0.052 0.14 0.332 ;
    END
  END QN
  PIN VDD
    DIRECTION INOUT ;
    USE POWER ;
    PORT
      LAYER M0 ;
        RECT -0.02 0.732 0.9 0.804 ;
        RECT -0.02 -0.036 0.9 0.036 ;
    END
  END VDD
  PIN VSS
    DIRECTION INOUT ;
    USE GROUND ;
    PORT
      LAYER M0 ;
        RECT -0.02 0.348 0.9 0.42 ;
    END
  END VSS
  OBS
    LAYER M1 ;
      RECT 0.82 0.436 0.86 0.716 ;
      RECT 0.42 0.148 0.46 0.476 ;
      RECT 0.5 0.532 0.54 0.62 ;
      RECT 0.66 0.244 0.7 0.62 ;
      RECT 0.82 0.052 0.86 0.332 ;
      RECT 0.26 0.292 0.3 0.716 ;
      RECT 0.5 0.292 0.54 0.476 ;
      RECT 0.58 0.292 0.62 0.716 ;
      RECT 0.34 0.148 0.38 0.524 ;
      RECT 0.42 0.484 0.46 0.62 ;
      RECT 0.66 0.052 0.7 0.236 ;
      RECT 0.74 0.196 0.78 0.332 ;
      RECT 0.18 0.244 0.22 0.476 ;
      RECT 0.5 0.052 0.54 0.284 ;
    LAYER M0 ;
      RECT 0.628 0.492 0.852 0.516 ;
      RECT 0.508 0.588 0.692 0.612 ;
      RECT 0.468 0.54 0.532 0.564 ;
      RECT 0.428 0.444 0.492 0.468 ;
      RECT 0.388 0.3 0.452 0.324 ;
      RECT 0.668 0.252 0.852 0.276 ;
      RECT 0.428 0.156 0.492 0.18 ;
      RECT 0.068 0.492 0.292 0.516 ;
      RECT 0.268 0.3 0.332 0.324 ;
      RECT 0.508 0.684 0.812 0.708 ;
      RECT 0.508 0.3 0.612 0.324 ;
      RECT 0.428 0.588 0.492 0.612 ;
      RECT 0.348 0.492 0.572 0.516 ;
      RECT 0.668 0.3 0.772 0.324 ;
      RECT 0.348 0.204 0.772 0.228 ;
      RECT 0.348 0.156 0.412 0.18 ;
      RECT 0.188 0.444 0.252 0.468 ;
      RECT 0.068 0.252 0.532 0.276 ;
      RECT 0.428 0.06 0.532 0.084 ;
      RECT 0.828 0.684 0.852 0.708 ;
      RECT 0.828 0.444 0.852 0.468 ;
      RECT 0.828 0.3 0.852 0.324 ;
      RECT 0.828 0.06 0.852 0.084 ;
      RECT 0.268 0.684 0.292 0.708 ;
      RECT 0.268 0.444 0.292 0.468 ;
      RECT 0.508 0.444 0.532 0.468 ;
      RECT 0.668 0.06 0.692 0.084 ;
      RECT 0.748 0.06 0.812 0.084 ;
      RECT 0.348 0.54 0.412 0.564 ;
      RECT 0.108 0.444 0.132 0.468 ;
      RECT 0.108 0.684 0.132 0.708 ;
      RECT 0.108 0.06 0.132 0.084 ;
      RECT 0.108 0.3 0.132 0.324 ;
  END
END DFF_X2

MACRO DFFR_X1
  CLASS CORE ;
  FOREIGN DFFR_X1 0 0 ;
  SIZE 0.88 BY 0.768 ;
  ORIGIN 0.0 0.0 ;
  SYMMETRY X Y ;
  PIN CK
    DIRECTION INPUT ;
    USE CLOCK ;
    ANTENNAGATEAREA 0.00320 ;
    PORT
      LAYER M1 ;
        RECT 0.74 0.196 0.78 0.236 ;
    END
  END CK
  PIN D
    DIRECTION INPUT ;
    USE SIGNAL ;
    ANTENNAGATEAREA 0.00320 ;
    PORT
      LAYER M1 ;
        RECT 0.34 0.676 0.38 0.716 ;
    END
  END D
  PIN Q
    DIRECTION OUTPUT ;
    USE SIGNAL ;
    ANTENNADIFFAREA 0.0096 ;
    PORT
      LAYER M1 ;
        RECT 0.02 0.436 0.06 0.716 ;
    END
  END Q
  PIN QN
    DIRECTION OUTPUT ;
    USE SIGNAL ;
    ANTENNAGATEAREA 0.00640 ;
    ANTENNADIFFAREA 0.0096 ;
    PORT
      LAYER M1 ;
        RECT 0.02 0.052 0.06 0.332 ;
        RECT 0.1 0.244 0.14 0.524 ;
    END
  END QN
  PIN RN
    DIRECTION INPUT ;
    USE SIGNAL ;
    ANTENNAGATEAREA 0.00640 ;
    PORT
      LAYER M1 ;
        RECT 0.66 0.532 0.7 0.572 ;
        RECT 0.18 0.1 0.22 0.572 ;
    END
  END RN
  PIN VDD
    DIRECTION INOUT ;
    USE POWER ;
    PORT
      LAYER M0 ;
        RECT -0.02 -0.036 0.9 0.036 ;
        RECT -0.02 0.732 0.9 0.804 ;
    END
  END VDD
  PIN VSS
    DIRECTION INOUT ;
    USE GROUND ;
    PORT
      LAYER M0 ;
        RECT -0.02 0.348 0.9 0.42 ;
    END
  END VSS
  OBS
    LAYER M1 ;
      RECT 0.42 0.148 0.46 0.236 ;
      RECT 0.82 0.052 0.86 0.332 ;
      RECT 0.34 0.1 0.38 0.668 ;
      RECT 0.66 0.052 0.7 0.476 ;
      RECT 0.82 0.436 0.86 0.716 ;
      RECT 0.26 0.052 0.3 0.331 ;
      RECT 0.5 0.196 0.54 0.62 ;
      RECT 0.58 0.292 0.62 0.716 ;
    LAYER M0 ;
      RECT 0.148 0.06 0.452 0.084 ;
      RECT 0.268 0.3 0.452 0.324 ;
      RECT 0.348 0.108 0.852 0.132 ;
      RECT 0.428 0.204 0.532 0.228 ;
      RECT 0.348 0.252 0.452 0.276 ;
      RECT 0.388 0.156 0.452 0.18 ;
      RECT 0.708 0.252 0.852 0.276 ;
      RECT 0.548 0.3 0.612 0.324 ;
      RECT 0.668 0.3 0.692 0.324 ;
      RECT 0.668 0.06 0.692 0.084 ;
      RECT 0.828 0.3 0.852 0.324 ;
      RECT 0.828 0.06 0.852 0.084 ;
      RECT 0.508 0.636 0.692 0.66 ;
      RECT 0.505 0.204 0.692 0.228 ;
      RECT 0.348 0.636 0.492 0.66 ;
      RECT 0.428 0.684 0.81 0.708 ;
      RECT 0.548 0.588 0.852 0.612 ;
      RECT 0.468 0.444 0.692 0.468 ;
      RECT 0.428 0.492 0.612 0.516 ;
      RECT 0.388 0.588 0.533 0.612 ;
      RECT 0.347 0.444 0.412 0.468 ;
      RECT 0.828 0.684 0.852 0.708 ;
      RECT 0.828 0.444 0.852 0.468 ;
      RECT 0.748 0.204 0.812 0.228 ;
      RECT 0.308 0.684 0.372 0.708 ;
      RECT 0.028 0.444 0.052 0.468 ;
      RECT 0.028 0.684 0.052 0.708 ;
      RECT 0.028 0.3 0.132 0.324 ;
      RECT 0.028 0.06 0.132 0.084 ;
      RECT 0.108 0.252 0.332 0.276 ;
      RECT 0.068 0.492 0.132 0.516 ;
      RECT 0.628 0.54 0.692 0.564 ;
      RECT 0.188 0.54 0.65 0.564 ;
      RECT 0.068 0.108 0.212 0.132 ;
  END
END DFFR_X1

MACRO DLH_X1
  CLASS CORE ;
  FOREIGN DLH_X1 0 0 ;
  SIZE 0.64 BY 0.768 ;
  ORIGIN 0.0 0.0 ;
  SYMMETRY X Y ;
  PIN CK
    DIRECTION INPUT ;
    USE CLOCK ;
    ANTENNAGATEAREA 0.00320 ;
    PORT
      LAYER M1 ;
        RECT 0.1 0.052 0.14 0.119 ;
    END
  END CK
  PIN D
    DIRECTION INPUT ;
    USE SIGNAL ;
    ANTENNAGATEAREA 0.00320 ;
    PORT
      LAYER M1 ;
        RECT 0.1 0.505 0.14 0.572 ;
    END
  END D
  PIN Q
    DIRECTION OUTPUT ;
    USE SIGNAL ;
    ANTENNADIFFAREA 0.0096 ;
    PORT
      LAYER M1 ;
        RECT 0.58 0.052 0.62 0.332 ;
    END
  END Q
  PIN QN
    DIRECTION OUTPUT ;
    USE SIGNAL ;
    ANTENNADIFFAREA 0.0096 ;
    PORT
      LAYER M1 ;
        RECT 0.58 0.436 0.62 0.716 ;
    END
  END QN
  PIN VDD
    DIRECTION INOUT ;
    USE POWER ;
    PORT
      LAYER M0 ;
        RECT -0.02 -0.036 0.66 0.036 ;
        RECT -0.02 0.732 0.66 0.804 ;
    END
  END VDD
  PIN VSS
    DIRECTION INOUT ;
    USE GROUND ;
    PORT
      LAYER M0 ;
        RECT -0.02 0.348 0.66 0.42 ;
    END
  END VSS
  OBS
    LAYER M1 ;
      RECT 0.18 0.052 0.22 0.572 ;
      RECT 0.5 0.292 0.54 0.572 ;
      RECT 0.42 0.052 0.46 0.332 ;
      RECT 0.02 0.052 0.06 0.62 ;
      RECT 0.26 0.436 0.3 0.716 ;
      RECT 0.42 0.436 0.46 0.716 ;
      RECT 0.34 0.292 0.38 0.476 ;
    LAYER M0 ;
      RECT 0.42 0.06 0.46 0.084 ;
      RECT 0.02 0.06 0.06 0.084 ;
      RECT 0.028 0.108 0.412 0.132 ;
      RECT 0.268 0.54 0.532 0.564 ;
      RECT 0.26 0.444 0.3 0.468 ;
      RECT 0.348 0.444 0.452 0.468 ;
      RECT 0.188 0.54 0.252 0.564 ;
      RECT 0.18 0.3 0.22 0.324 ;
      RECT 0.02 0.3 0.06 0.324 ;
      RECT 0.188 0.06 0.412 0.084 ;
      RECT 0.428 0.684 0.572 0.708 ;
      RECT 0.428 0.3 0.572 0.324 ;
      RECT 0.268 0.684 0.412 0.708 ;
      RECT 0.308 0.3 0.372 0.324 ;
      RECT 0.028 0.588 0.252 0.612 ;
      RECT 0.068 0.06 0.132 0.084 ;
      RECT 0.108 0.54 0.172 0.564 ;
      RECT 0.58 0.06 0.62 0.084 ;
      RECT 0.588 0.3 0.62 0.324 ;
      RECT 0.58 0.684 0.62 0.708 ;
      RECT 0.58 0.444 0.62 0.468 ;
  END
END DLH_X1

MACRO FA_X1
  CLASS CORE ;
  FOREIGN FA_X1 0 0 ;
  SIZE 0.88 BY 0.768 ;
  ORIGIN 0.0 0.0 ;
  SYMMETRY X Y ;
  PIN A
    DIRECTION INPUT ;
    USE SIGNAL ;
    ANTENNAGATEAREA 0.00640 ;
    PORT
      LAYER M1 ;
        RECT 0.18 0.196 0.22 0.524 ;
    END
  END A
  PIN B
    DIRECTION INPUT ;
    USE SIGNAL ;
    ANTENNAGATEAREA 0.01280 ;
    PORT
      LAYER M1 ;
        RECT 0.02 0.104 0.06 0.476 ;
        RECT 0.26 0.196 0.3 0.476 ;
        RECT 0.66 0.1 0.7 0.476 ;
    END
  END B
  PIN CI
    DIRECTION INPUT ;
    USE SIGNAL ;
    ANTENNAGATEAREA 0.00960 ;
    PORT
      LAYER M1 ;
        RECT 0.34 0.292 0.38 0.476 ;
        RECT 0.58 0.292 0.62 0.476 ;
    END
  END CI
  PIN CO
    DIRECTION OUTPUT ;
    USE SIGNAL ;
    ANTENNADIFFAREA 0.0096 ;
    PORT
      LAYER M1 ;
        RECT 0.42 0.052 0.46 0.332 ;
    END
  END CO
  PIN S
    DIRECTION INPUT ;
    USE SIGNAL ;
    ANTENNADIFFAREA 0.0096 ;
    PORT
      LAYER M1 ;
        RECT 0.34 0.484 0.38 0.716 ;
    END
  END S
  PIN VDD
    DIRECTION INOUT ;
    USE POWER ;
    PORT
      LAYER M0 ;
        RECT -0.02 0.732 0.9 0.804 ;
        RECT -0.02 -0.036 0.9 0.036 ;
    END
  END VDD
  PIN VSS
    DIRECTION INOUT ;
    USE GROUND ;
    PORT
      LAYER M0 ;
        RECT -0.02 0.348 0.9 0.42 ;
    END
  END VSS
  OBS
    LAYER M1 ;
      RECT 0.74 0.1 0.78 0.572 ;
      RECT 0.1 0.148 0.14 0.284 ;
      RECT 0.26 0.484 0.3 0.716 ;
      RECT 0.26 0.052 0.3 0.188 ;
      RECT 0.82 0.148 0.86 0.62 ;
      RECT 0.5 0.052 0.54 0.716 ;
    LAYER M0 ;
      RECT 0.028 0.06 0.212 0.084 ;
      RECT 0.748 0.252 0.772 0.324 ;
      RECT 0.228 0.54 0.772 0.564 ;
      RECT 0.748 0.108 0.812 0.132 ;
      RECT 0.268 0.588 0.852 0.612 ;
      RECT 0.108 0.252 0.292 0.276 ;
      RECT 0.108 0.156 0.852 0.18 ;
      RECT 0.588 0.06 0.772 0.084 ;
      RECT 0.388 0.636 0.532 0.66 ;
      RECT 0.028 0.3 0.212 0.324 ;
      RECT 0.268 0.684 0.292 0.708 ;
      RECT 0.268 0.492 0.292 0.516 ;
      RECT 0.268 0.06 0.292 0.084 ;
      RECT 0.508 0.684 0.532 0.708 ;
      RECT 0.508 0.492 0.532 0.516 ;
      RECT 0.508 0.3 0.532 0.324 ;
      RECT 0.508 0.06 0.532 0.084 ;
      RECT 0.588 0.252 0.772 0.276 ;
      RECT 0.15 0.204 0.212 0.228 ;
      RECT 0.188 0.492 0.252 0.516 ;
      RECT 0.028 0.444 0.292 0.468 ;
      RECT 0.028 0.109 0.092 0.133 ;
      RECT 0.348 0.204 0.692 0.228 ;
      RECT 0.268 0.204 0.372 0.228 ;
      RECT 0.668 0.108 0.73 0.132 ;
      RECT 0.628 0.444 0.692 0.468 ;
      RECT 0.348 0.444 0.612 0.468 ;
      RECT 0.228 0.3 0.372 0.324 ;
      RECT 0.588 0.3 0.652 0.324 ;
      RECT 0.428 0.06 0.452 0.084 ;
      RECT 0.428 0.3 0.452 0.324 ;
      RECT 0.348 0.684 0.372 0.708 ;
      RECT 0.348 0.492 0.372 0.516 ;
  END
END FA_X1

MACRO HA_X1
  CLASS CORE ;
  FOREIGN HA_X1 0 0 ;
  SIZE 0.48 BY 0.768 ;
  ORIGIN 0.0 0.0 ;
  SYMMETRY X Y ;
  PIN A
    DIRECTION INPUT ;
    USE SIGNAL ;
    ANTENNAGATEAREA 0.00960 ;
    PORT
      LAYER M1 ;
        RECT 0.26 0.244 0.3 0.476 ;
    END
  END A
  PIN B
    DIRECTION INPUT ;
    USE SIGNAL ;
    ANTENNAGATEAREA 0.00960 ;
    PORT
      LAYER M1 ;
        RECT 0.18 0.196 0.22 0.476 ;
    END
  END B
  PIN CO
    DIRECTION OUTPUT ;
    USE SIGNAL ;
    ANTENNADIFFAREA 0.0096 ;
    PORT
      LAYER M1 ;
        RECT 0.34 0.484 0.38 0.716 ;
    END
  END CO
  PIN S
    DIRECTION INPUT ;
    USE SIGNAL ;
    ANTENNADIFFAREA 0.0144 ;
    PORT
      LAYER M1 ;
        RECT 0.18 0.484 0.22 0.668 ;
    END
  END S
  PIN VDD
    DIRECTION INOUT ;
    USE POWER ;
    PORT
      LAYER M0 ;
        RECT -0.02 0.732 0.5 0.804 ;
        RECT -0.02 -0.036 0.5 0.036 ;
    END
  END VDD
  PIN VSS
    DIRECTION INOUT ;
    USE GROUND ;
    PORT
      LAYER M0 ;
        RECT -0.02 0.348 0.5 0.42 ;
    END
  END VSS
  OBS
    LAYER M1 ;
      RECT 0.34 0.052 0.38 0.476 ;
      RECT 0.42 0.052 0.46 0.476 ;
      RECT 0.02 0.052 0.06 0.476 ;
      RECT 0.1 0.292 0.14 0.476 ;
    LAYER M0 ;
      RECT 0.348 0.444 0.452 0.468 ;
      RECT 0.268 0.06 0.372 0.084 ;
      RECT 0.028 0.444 0.132 0.468 ;
      RECT 0.108 0.3 0.212 0.324 ;
      RECT 0.108 0.684 0.292 0.708 ;
      RECT 0.428 0.3 0.452 0.324 ;
      RECT 0.428 0.06 0.452 0.084 ;
      RECT 0.028 0.3 0.052 0.324 ;
      RECT 0.028 0.06 0.052 0.084 ;
      RECT 0.148 0.252 0.412 0.276 ;
      RECT 0.228 0.444 0.292 0.468 ;
      RECT 0.148 0.444 0.212 0.468 ;
      RECT 0.068 0.204 0.332 0.228 ;
      RECT 0.348 0.684 0.372 0.708 ;
      RECT 0.348 0.492 0.372 0.516 ;
      RECT 0.028 0.492 0.292 0.516 ;
      RECT 0.188 0.636 0.212 0.66 ;
  END
END HA_X1

MACRO INV_X1
  CLASS CORE ;
  FOREIGN INV_X1 0 0 ;
  SIZE 0.16 BY 0.384 ;
  ORIGIN 0.0 0.0 ;
  SYMMETRY X Y ;
  PIN A
    DIRECTION INPUT ;
    USE SIGNAL ;
    ANTENNAGATEAREA 0.00320 ;
    PORT
      LAYER M1 ;
        RECT 0.02 0.196 0.06 0.236 ;
    END
  END A
  PIN ZN
    DIRECTION OUTPUT ;
    USE SIGNAL ;
    ANTENNADIFFAREA 0.0096 ;
    PORT
      LAYER M1 ;
        RECT 0.1 0.052 0.14 0.332 ;
    END
  END ZN
  PIN VDD
    DIRECTION INOUT ;
    USE POWER ;
    PORT
      LAYER M0 ;
        RECT -0.02 0.348 0.18 0.42 ;
    END
  END VDD
  PIN VSS
    DIRECTION INOUT ;
    USE GROUND ;
    PORT
      LAYER M0 ;
        RECT -0.02 -0.036 0.18 0.036 ;
    END
  END VSS
  OBS
    LAYER M0 ;
      RECT 0.028 0.204 0.092 0.228 ;
      RECT 0.108 0.06 0.132 0.084 ;
      RECT 0.108 0.3 0.132 0.324 ;
  END
END INV_X1

MACRO INV_X2
  CLASS CORE ;
  FOREIGN INV_X2 0 0 ;
  SIZE 0.24 BY 0.384 ;
  ORIGIN 0.0 0.0 ;
  SYMMETRY X Y ;
  PIN A
    DIRECTION INPUT ;
    USE SIGNAL ;
    ANTENNAGATEAREA 0.00640 ;
    PORT
      LAYER M1 ;
        RECT 0.18 0.196 0.22 0.284 ;
    END
  END A
  PIN ZN
    DIRECTION OUTPUT ;
    USE SIGNAL ;
    ANTENNADIFFAREA 0.0096 ;
    PORT
      LAYER M1 ;
        RECT 0.1 0.052 0.14 0.332 ;
    END
  END ZN
  PIN VDD
    DIRECTION INOUT ;
    USE POWER ;
    PORT
      LAYER M0 ;
        RECT -0.02 0.348 0.26 0.42 ;
    END
  END VDD
  PIN VSS
    DIRECTION INOUT ;
    USE GROUND ;
    PORT
      LAYER M0 ;
        RECT -0.02 -0.036 0.26 0.036 ;
    END
  END VSS
  OBS
    LAYER M0 ;
      RECT 0.148 0.204 0.212 0.228 ;
      RECT 0.068 0.252 0.212 0.276 ;
      RECT 0.108 0.06 0.132 0.084 ;
      RECT 0.108 0.3 0.132 0.324 ;
  END
END INV_X2

MACRO INV_X4
  CLASS CORE ;
  FOREIGN INV_X4 0 0 ;
  SIZE 0.4 BY 0.384 ;
  ORIGIN 0.0 0.0 ;
  SYMMETRY X Y ;
  PIN A
    DIRECTION INPUT ;
    USE SIGNAL ;
    ANTENNAGATEAREA 0.01280 ;
    PORT
      LAYER M1 ;
        RECT 0.1 0.148 0.14 0.188 ;
    END
  END A
  PIN ZN
    DIRECTION OUTPUT ;
    USE SIGNAL ;
    ANTENNADIFFAREA 0.0288 ;
    PORT
      LAYER M1 ;
        RECT 0.02 0.052 0.06 0.332 ;
        RECT 0.18 0.052 0.22 0.332 ;
        RECT 0.34 0.052 0.38 0.332 ;
    END
  END ZN
  PIN VDD
    DIRECTION INOUT ;
    USE POWER ;
    PORT
      LAYER M0 ;
        RECT -0.02 0.348 0.42 0.42 ;
    END
  END VDD
  PIN VSS
    DIRECTION INOUT ;
    USE GROUND ;
    PORT
      LAYER M0 ;
        RECT -0.02 -0.036 0.42 0.036 ;
    END
  END VSS
  OBS
    LAYER M0 ;
      RECT 0.068 0.156 0.332 0.18 ;
      RECT 0.028 0.06 0.052 0.084 ;
      RECT 0.028 0.204 0.372 0.228 ;
      RECT 0.028 0.3 0.052 0.324 ;
      RECT 0.188 0.06 0.212 0.084 ;
      RECT 0.188 0.3 0.212 0.324 ;
      RECT 0.348 0.3 0.372 0.324 ;
      RECT 0.348 0.06 0.372 0.084 ;
  END
END INV_X4

MACRO INV_X8
  CLASS CORE ;
  FOREIGN INV_X8 0 0 ;
  SIZE 0.72 BY 0.384 ;
  ORIGIN 0.0 0.0 ;
  SYMMETRY X Y ;
  PIN A
    DIRECTION INPUT ;
    USE SIGNAL ;
    ANTENNAGATEAREA 0.02560 ;
    PORT
      LAYER M1 ;
        RECT 0.1 0.148 0.14 0.188 ;
    END
  END A
  PIN ZN
    DIRECTION OUTPUT ;
    USE SIGNAL ;
    ANTENNADIFFAREA 0.0480 ;
    PORT
      LAYER M1 ;
        RECT 0.02 0.052 0.06 0.332 ;
        RECT 0.18 0.052 0.22 0.332 ;
        RECT 0.66 0.052 0.7 0.332 ;
        RECT 0.34 0.052 0.38 0.332 ;
        RECT 0.5 0.052 0.54 0.332 ;
    END
  END ZN
  PIN VDD
    DIRECTION INOUT ;
    USE POWER ;
    PORT
      LAYER M0 ;
        RECT 0.3 0.348 0.74 0.42 ;
        RECT -0.02 0.348 0.42 0.42 ;
    END
  END VDD
  PIN VSS
    DIRECTION INOUT ;
    USE GROUND ;
    PORT
      LAYER M0 ;
        RECT 0.3 -0.036 0.74 0.036 ;
        RECT -0.02 -0.036 0.42 0.036 ;
    END
  END VSS
  OBS
    LAYER M0 ;
      RECT 0.388 0.156 0.652 0.18 ;
      RECT 0.068 0.156 0.41 0.18 ;
      RECT 0.028 0.06 0.052 0.084 ;
      RECT 0.348 0.204 0.692 0.228 ;
      RECT 0.028 0.3 0.052 0.324 ;
      RECT 0.028 0.204 0.372 0.228 ;
      RECT 0.668 0.06 0.692 0.084 ;
      RECT 0.348 0.3 0.372 0.324 ;
      RECT 0.508 0.06 0.532 0.084 ;
      RECT 0.508 0.3 0.532 0.324 ;
      RECT 0.668 0.3 0.692 0.324 ;
      RECT 0.348 0.06 0.372 0.084 ;
      RECT 0.188 0.3 0.212 0.324 ;
      RECT 0.188 0.06 0.212 0.084 ;
  END
END INV_X8

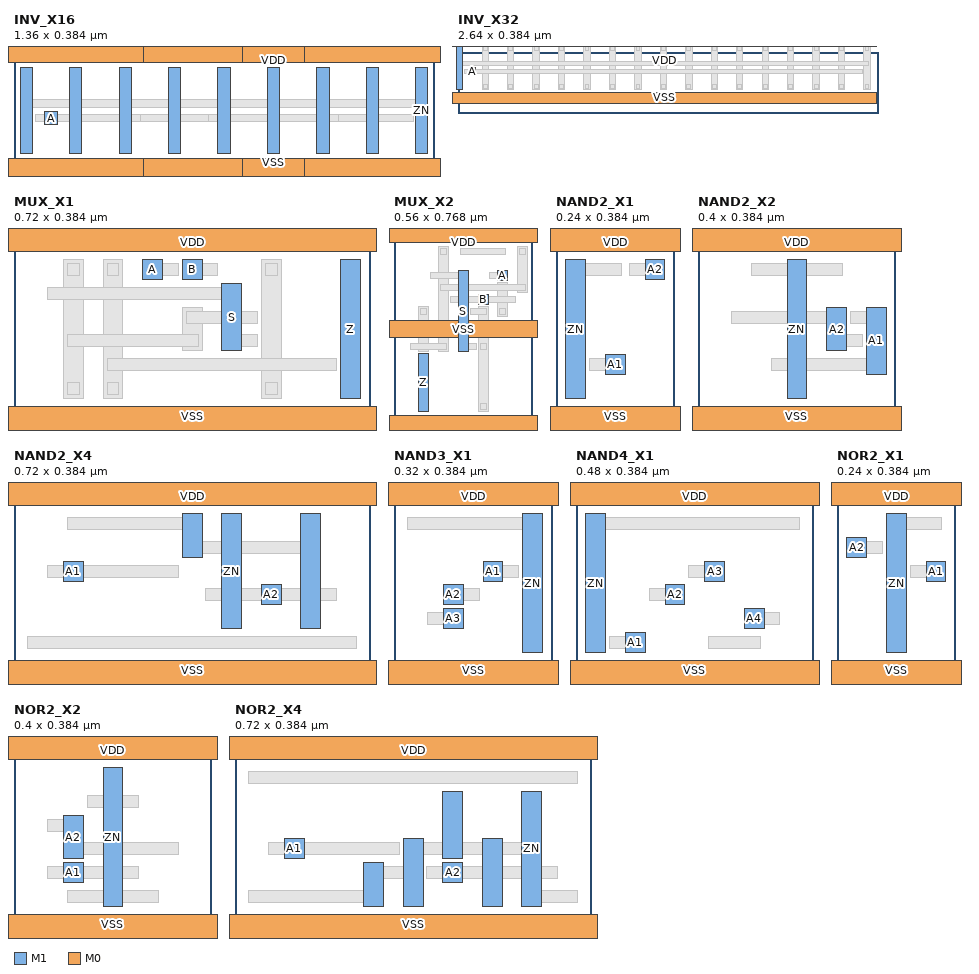
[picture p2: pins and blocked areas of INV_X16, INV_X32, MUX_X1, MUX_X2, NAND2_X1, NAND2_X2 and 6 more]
MACRO INV_X16
  CLASS CORE ;
  FOREIGN INV_X16 0 0 ;
  SIZE 1.36 BY 0.384 ;
  ORIGIN 0.0 0.0 ;
  SYMMETRY X Y ;
  PIN A
    DIRECTION INPUT ;
    USE SIGNAL ;
    ANTENNAGATEAREA 0.05120 ;
    PORT
      LAYER M1 ;
        RECT 0.1 0.148 0.14 0.188 ;
    END
  END A
  PIN ZN
    DIRECTION OUTPUT ;
    USE SIGNAL ;
    ANTENNADIFFAREA 0.0864 ;
    PORT
      LAYER M1 ;
        RECT 0.02 0.052 0.06 0.332 ;
        RECT 0.34 0.052 0.38 0.332 ;
        RECT 0.66 0.052 0.7 0.332 ;
        RECT 1.3 0.052 1.34 0.332 ;
        RECT 0.82 0.052 0.86 0.332 ;
        RECT 0.98 0.052 1.02 0.332 ;
        RECT 0.18 0.052 0.22 0.332 ;
        RECT 0.5 0.052 0.54 0.332 ;
        RECT 1.14 0.052 1.18 0.332 ;
    END
  END ZN
  PIN VDD
    DIRECTION INOUT ;
    USE POWER ;
    PORT
      LAYER M0 ;
        RECT 0.62 0.348 1.06 0.42 ;
        RECT 0.3 0.348 0.74 0.42 ;
        RECT -0.02 0.348 0.42 0.42 ;
        RECT 0.94 0.348 1.38 0.42 ;
    END
  END VDD
  PIN VSS
    DIRECTION INOUT ;
    USE GROUND ;
    PORT
      LAYER M0 ;
        RECT 0.62 -0.036 1.06 0.036 ;
        RECT 0.3 -0.036 0.74 0.036 ;
        RECT -0.02 -0.036 0.42 0.036 ;
        RECT 0.94 -0.036 1.38 0.036 ;
    END
  END VSS
  OBS
    LAYER M0 ;
      RECT 0.388 0.156 0.652 0.18 ;
      RECT 1.028 0.156 1.292 0.18 ;
      RECT 0.63 0.156 1.05 0.18 ;
      RECT 0.068 0.156 0.41 0.18 ;
      RECT 0.028 0.06 0.052 0.084 ;
      RECT 0.988 0.204 1.332 0.228 ;
      RECT 0.668 0.204 1.012 0.228 ;
      RECT 0.028 0.3 0.052 0.324 ;
      RECT 0.028 0.204 0.372 0.228 ;
      RECT 0.348 0.204 0.692 0.228 ;
      RECT 0.668 0.06 0.692 0.084 ;
      RECT 0.828 0.3 0.852 0.324 ;
      RECT 0.348 0.3 0.372 0.324 ;
      RECT 1.308 0.06 1.332 0.084 ;
      RECT 0.508 0.06 0.532 0.084 ;
      RECT 0.508 0.3 0.532 0.324 ;
      RECT 0.668 0.3 0.692 0.324 ;
      RECT 1.148 0.06 1.172 0.084 ;
      RECT 0.828 0.06 0.852 0.084 ;
      RECT 0.348 0.06 0.372 0.084 ;
      RECT 0.988 0.06 1.012 0.084 ;
      RECT 0.988 0.3 1.012 0.324 ;
      RECT 1.148 0.3 1.172 0.324 ;
      RECT 0.188 0.3 0.212 0.324 ;
      RECT 1.308 0.3 1.332 0.324 ;
      RECT 0.188 0.06 0.212 0.084 ;
  END
END INV_X16

MACRO INV_X32
  CLASS CORE ;
  ORIGIN 0 0 ;
  FOREIGN INV_X32 0 0 ;
  SIZE 2.64 BY 0.384 ;
  PIN VDD
    DIRECTION INOUT ;
    USE POWER ;
    PORT
      LAYER M0 ;
        RECT -0.049 0.443 2.631 0.515 ;
    END
  END VDD
  PIN VSS
    DIRECTION INOUT ;
    USE GROUND ;
    PORT
      LAYER M0 ;
        RECT -0.049 0.059 2.631 0.131 ;
    END
  END VSS
  PIN A
    DIRECTION INOUT ;
    USE SIGNAL ;
    PORT
      LAYER M1 ;
        RECT 0.071 0.243 0.111 0.283 ;
    END
  END A
  PIN ZN
    DIRECTION INOUT ;
    USE SIGNAL ;
    PORT
      LAYER M1 ;
        RECT -0.009 0.147 0.031 0.427 ;
    END
  END ZN
  OBS
    LAYER M1 SPACING 0 ;
      RECT 0.151 0.147 0.191 0.427 ;
      RECT 0.311 0.147 0.351 0.427 ;
      RECT 0.471 0.147 0.511 0.427 ;
      RECT 0.631 0.147 0.671 0.427 ;
      RECT 0.791 0.147 0.831 0.427 ;
      RECT 0.951 0.147 0.991 0.427 ;
      RECT 1.111 0.147 1.151 0.427 ;
      RECT 1.271 0.147 1.311 0.427 ;
      RECT 1.431 0.147 1.471 0.427 ;
      RECT 1.591 0.147 1.631 0.427 ;
      RECT 1.751 0.147 1.791 0.427 ;
      RECT 1.911 0.147 1.951 0.427 ;
      RECT 2.071 0.147 2.111 0.427 ;
      RECT 2.231 0.147 2.271 0.427 ;
      RECT 2.391 0.147 2.431 0.427 ;
      RECT 2.551 0.147 2.591 0.427 ;
    LAYER M0 SPACING 0 ;
      RECT -0.001 0.155 0.023 0.179 ;
      RECT 0.159 0.155 0.183 0.179 ;
      RECT 0.319 0.155 0.343 0.179 ;
      RECT 0.479 0.155 0.503 0.179 ;
      RECT 0.639 0.155 0.663 0.179 ;
      RECT 0.799 0.155 0.823 0.179 ;
      RECT 0.959 0.155 0.983 0.179 ;
      RECT 1.119 0.155 1.143 0.179 ;
      RECT 1.279 0.155 1.303 0.179 ;
      RECT 1.439 0.155 1.463 0.179 ;
      RECT 1.599 0.155 1.623 0.179 ;
      RECT 1.759 0.155 1.783 0.179 ;
      RECT 1.919 0.155 1.943 0.179 ;
      RECT 2.079 0.155 2.103 0.179 ;
      RECT 2.239 0.155 2.263 0.179 ;
      RECT 2.399 0.155 2.423 0.179 ;
      RECT 2.559 0.155 2.583 0.179 ;
      RECT 0.039 0.251 2.543 0.275 ;
      RECT -0.001 0.299 2.583 0.323 ;
      RECT -0.001 0.395 0.023 0.419 ;
      RECT 0.159 0.395 0.183 0.419 ;
      RECT 0.319 0.395 0.343 0.419 ;
      RECT 0.479 0.395 0.503 0.419 ;
      RECT 0.639 0.395 0.663 0.419 ;
      RECT 0.799 0.395 0.823 0.419 ;
      RECT 0.959 0.395 0.983 0.419 ;
      RECT 1.119 0.395 1.143 0.419 ;
      RECT 1.279 0.395 1.303 0.419 ;
      RECT 1.439 0.395 1.463 0.419 ;
      RECT 1.599 0.395 1.623 0.419 ;
      RECT 1.759 0.395 1.783 0.419 ;
      RECT 1.919 0.395 1.943 0.419 ;
      RECT 2.079 0.395 2.103 0.419 ;
      RECT 2.239 0.395 2.263 0.419 ;
      RECT 2.399 0.395 2.423 0.419 ;
      RECT 2.559 0.395 2.583 0.419 ;
  END
END INV_X32


MACRO MUX_X1
  CLASS CORE ;
  FOREIGN MUX_X1 0 0 ;
  SIZE 0.72 BY 0.384 ;
  ORIGIN 0.0 0.0 ;
  SYMMETRY X Y ;
  PIN A
    DIRECTION INPUT ;
    USE SIGNAL ;
    ANTENNAGATEAREA 0.00320 ;
    PORT
      LAYER M1 ;
        RECT 0.26 0.292 0.3 0.332 ;
    END
  END A
  PIN B
    DIRECTION INPUT ;
    USE SIGNAL ;
    ANTENNAGATEAREA 0.00320 ;
    PORT
      LAYER M1 ;
        RECT 0.34 0.292 0.38 0.332 ;
    END
  END B
  PIN S
    DIRECTION INPUT ;
    USE SIGNAL ;
    ANTENNAGATEAREA 0.00640 ;
    PORT
      LAYER M1 ;
        RECT 0.42 0.148 0.46 0.284 ;
    END
  END S
  PIN Z
    DIRECTION OUTPUT ;
    USE SIGNAL ;
    ANTENNADIFFAREA 0.0096 ;
    PORT
      LAYER M1 ;
        RECT 0.66 0.052 0.7 0.332 ;
    END
  END Z
  PIN VDD
    DIRECTION INOUT ;
    USE POWER ;
    PORT
      LAYER M0 ;
        RECT -0.02 0.348 0.74 0.42 ;
    END
  END VDD
  PIN VSS
    DIRECTION INOUT ;
    USE GROUND ;
    PORT
      LAYER M0 ;
        RECT -0.02 -0.036 0.74 0.036 ;
    END
  END VSS
  OBS
    LAYER M1 ;
      RECT 0.1 0.052 0.14 0.332 ;
      RECT 0.34 0.148 0.38 0.236 ;
      RECT 0.18 0.052 0.22 0.332 ;
      RECT 0.5 0.052 0.54 0.332 ;
    LAYER M0 ;
      RECT 0.348 0.204 0.492 0.228 ;
      RECT 0.108 0.156 0.372 0.18 ;
      RECT 0.188 0.108 0.652 0.132 ;
      RECT 0.108 0.3 0.132 0.324 ;
      RECT 0.108 0.06 0.132 0.084 ;
      RECT 0.188 0.3 0.212 0.324 ;
      RECT 0.508 0.3 0.532 0.324 ;
      RECT 0.188 0.06 0.212 0.084 ;
      RECT 0.508 0.06 0.532 0.084 ;
      RECT 0.268 0.3 0.332 0.324 ;
      RECT 0.348 0.3 0.412 0.324 ;
      RECT 0.068 0.252 0.452 0.276 ;
      RECT 0.428 0.156 0.492 0.18 ;
      RECT 0.668 0.06 0.692 0.084 ;
      RECT 0.668 0.3 0.692 0.324 ;
  END
END MUX_X1

MACRO MUX_X2
  CLASS CORE ;
  FOREIGN MUX_X2 0 0 ;
  SIZE 0.56 BY 0.768 ;
  ORIGIN 0.0 0.0 ;
  SYMMETRY X Y ;
  PIN A
    DIRECTION INPUT ;
    USE SIGNAL ;
    ANTENNAGATEAREA 0.00320 ;
    PORT
      LAYER M1 ;
        RECT 0.42 0.58 0.46 0.62 ;
    END
  END A
  PIN B
    DIRECTION INPUT ;
    USE SIGNAL ;
    ANTENNAGATEAREA 0.00480 ;
    PORT
      LAYER M1 ;
        RECT 0.34 0.484 0.38 0.524 ;
    END
  END B
  PIN S
    DIRECTION INPUT ;
    USE SIGNAL ;
    ANTENNAGATEAREA 0.00800 ;
    PORT
      LAYER M1 ;
        RECT 0.26 0.292 0.3 0.62 ;
    END
  END S
  PIN Z
    DIRECTION OUTPUT ;
    USE SIGNAL ;
    ANTENNADIFFAREA 0.0096 ;
    PORT
      LAYER M1 ;
        RECT 0.1 0.052 0.14 0.284 ;
    END
  END Z
  PIN VDD
    DIRECTION INOUT ;
    USE POWER ;
    PORT
      LAYER M0 ;
        RECT -0.02 0.732 0.58 0.804 ;
        RECT -0.02 -0.036 0.58 0.036 ;
    END
  END VDD
  PIN VSS
    DIRECTION INOUT ;
    USE GROUND ;
    PORT
      LAYER M0 ;
        RECT -0.02 0.348 0.58 0.42 ;
    END
  END VSS
  OBS
    LAYER M1 ;
      RECT 0.1 0.292 0.14 0.476 ;
      RECT 0.18 0.292 0.22 0.716 ;
      RECT 0.42 0.436 0.46 0.572 ;
      RECT 0.5 0.532 0.54 0.716 ;
      RECT 0.34 0.052 0.38 0.476 ;
    LAYER M0 ;
      RECT 0.268 0.684 0.452 0.708 ;
      RECT 0.188 0.54 0.532 0.564 ;
      RECT 0.068 0.3 0.212 0.324 ;
      RECT 0.308 0.444 0.372 0.468 ;
      RECT 0.188 0.684 0.212 0.708 ;
      RECT 0.508 0.684 0.532 0.708 ;
      RECT 0.108 0.444 0.132 0.468 ;
      RECT 0.428 0.444 0.452 0.468 ;
      RECT 0.348 0.3 0.372 0.324 ;
      RECT 0.348 0.06 0.372 0.084 ;
      RECT 0.388 0.588 0.452 0.612 ;
      RECT 0.228 0.492 0.492 0.516 ;
      RECT 0.268 0.3 0.332 0.324 ;
      RECT 0.148 0.588 0.292 0.612 ;
      RECT 0.108 0.252 0.132 0.276 ;
      RECT 0.108 0.06 0.132 0.084 ;
  END
END MUX_X2

MACRO NAND2_X1
  CLASS CORE ;
  FOREIGN NAND2_X1 0 0 ;
  SIZE 0.24 BY 0.384 ;
  ORIGIN 0.0 0.0 ;
  SYMMETRY X Y ;
  PIN A1
    DIRECTION INPUT ;
    USE SIGNAL ;
    ANTENNAGATEAREA 0.00320 ;
    PORT
      LAYER M1 ;
        RECT 0.1 0.1 0.14 0.14 ;
    END
  END A1
  PIN A2
    DIRECTION INPUT ;
    USE SIGNAL ;
    ANTENNAGATEAREA 0.00320 ;
    PORT
      LAYER M1 ;
        RECT 0.18 0.292 0.22 0.332 ;
    END
  END A2
  PIN ZN
    DIRECTION OUTPUT ;
    USE SIGNAL ;
    ANTENNADIFFAREA 0.0096 ;
    PORT
      LAYER M1 ;
        RECT 0.02 0.052 0.06 0.332 ;
    END
  END ZN
  PIN VDD
    DIRECTION INOUT ;
    USE POWER ;
    PORT
      LAYER M0 ;
        RECT -0.02 0.348 0.26 0.42 ;
    END
  END VDD
  PIN VSS
    DIRECTION INOUT ;
    USE GROUND ;
    PORT
      LAYER M0 ;
        RECT -0.02 -0.036 0.26 0.036 ;
    END
  END VSS
  OBS
    LAYER M0 ;
      RECT 0.068 0.108 0.132 0.132 ;
      RECT 0.148 0.3 0.212 0.324 ;
      RECT 0.028 0.06 0.052 0.084 ;
      RECT 0.028 0.3 0.132 0.324 ;
  END
END NAND2_X1

MACRO NAND2_X2
  CLASS CORE ;
  FOREIGN NAND2_X2 0 0 ;
  SIZE 0.4 BY 0.384 ;
  ORIGIN 0.0 0.0 ;
  SYMMETRY X Y ;
  PIN A1
    DIRECTION INPUT ;
    USE SIGNAL ;
    ANTENNAGATEAREA 0.00640 ;
    PORT
      LAYER M1 ;
        RECT 0.34 0.1 0.38 0.236 ;
    END
  END A1
  PIN A2
    DIRECTION INPUT ;
    USE SIGNAL ;
    ANTENNAGATEAREA 0.00640 ;
    PORT
      LAYER M1 ;
        RECT 0.26 0.148 0.3 0.236 ;
    END
  END A2
  PIN ZN
    DIRECTION OUTPUT ;
    USE SIGNAL ;
    ANTENNADIFFAREA 0.0144 ;
    PORT
      LAYER M1 ;
        RECT 0.18 0.052 0.22 0.332 ;
    END
  END ZN
  PIN VDD
    DIRECTION INOUT ;
    USE POWER ;
    PORT
      LAYER M0 ;
        RECT -0.02 0.348 0.42 0.42 ;
    END
  END VDD
  PIN VSS
    DIRECTION INOUT ;
    USE GROUND ;
    PORT
      LAYER M0 ;
        RECT -0.02 -0.036 0.42 0.036 ;
    END
  END VSS
  OBS
    LAYER M0 ;
      RECT 0.148 0.108 0.372 0.132 ;
      RECT 0.308 0.204 0.372 0.228 ;
      RECT 0.268 0.156 0.332 0.18 ;
      RECT 0.068 0.204 0.292 0.228 ;
      RECT 0.108 0.3 0.292 0.324 ;
      RECT 0.188 0.06 0.212 0.084 ;
  END
END NAND2_X2

MACRO NAND2_X4
  CLASS CORE ;
  FOREIGN NAND2_X4 0 0 ;
  SIZE 0.72 BY 0.384 ;
  ORIGIN 0.0 0.0 ;
  SYMMETRY X Y ;
  PIN A1
    DIRECTION INPUT ;
    USE SIGNAL ;
    ANTENNAGATEAREA 0.01280 ;
    PORT
      LAYER M1 ;
        RECT 0.1 0.196 0.14 0.236 ;
    END
  END A1
  PIN A2
    DIRECTION INPUT ;
    USE SIGNAL ;
    ANTENNAGATEAREA 0.01280 ;
    PORT
      LAYER M1 ;
        RECT 0.5 0.148 0.54 0.188 ;
    END
  END A2
  PIN ZN
    DIRECTION OUTPUT ;
    USE SIGNAL ;
    ANTENNADIFFAREA 0.0288 ;
    PORT
      LAYER M1 ;
        RECT 0.34 0.244 0.38 0.332 ;
        RECT 0.42 0.1 0.46 0.332 ;
        RECT 0.58 0.1 0.62 0.332 ;
    END
  END ZN
  PIN VDD
    DIRECTION INOUT ;
    USE POWER ;
    PORT
      LAYER M0 ;
        RECT -0.02 0.348 0.74 0.42 ;
    END
  END VDD
  PIN VSS
    DIRECTION INOUT ;
    USE GROUND ;
    PORT
      LAYER M0 ;
        RECT -0.02 -0.036 0.74 0.036 ;
    END
  END VSS
  OBS
    LAYER M0 ;
      RECT 0.028 0.06 0.692 0.084 ;
      RECT 0.068 0.204 0.332 0.228 ;
      RECT 0.388 0.156 0.652 0.18 ;
      RECT 0.108 0.3 0.372 0.324 ;
      RECT 0.348 0.252 0.612 0.276 ;
      RECT 0.428 0.108 0.452 0.132 ;
      RECT 0.588 0.108 0.612 0.132 ;
      RECT 0.588 0.3 0.612 0.324 ;
      RECT 0.428 0.3 0.452 0.324 ;
  END
END NAND2_X4

MACRO NAND3_X1
  CLASS CORE ;
  FOREIGN NAND3_X1 0 0 ;
  SIZE 0.32 BY 0.384 ;
  ORIGIN 0.0 0.0 ;
  SYMMETRY X Y ;
  PIN A1
    DIRECTION INPUT ;
    USE SIGNAL ;
    ANTENNAGATEAREA 0.00320 ;
    PORT
      LAYER M1 ;
        RECT 0.18 0.196 0.22 0.236 ;
    END
  END A1
  PIN A2
    DIRECTION INPUT ;
    USE SIGNAL ;
    ANTENNAGATEAREA 0.00320 ;
    PORT
      LAYER M1 ;
        RECT 0.1 0.148 0.14 0.188 ;
    END
  END A2
  PIN A3
    DIRECTION INPUT ;
    USE SIGNAL ;
    ANTENNAGATEAREA 0.00320 ;
    PORT
      LAYER M1 ;
        RECT 0.1 0.1 0.14 0.14 ;
    END
  END A3
  PIN ZN
    DIRECTION OUTPUT ;
    USE SIGNAL ;
    ANTENNADIFFAREA 0.0144 ;
    PORT
      LAYER M1 ;
        RECT 0.26 0.052 0.3 0.332 ;
    END
  END ZN
  PIN VDD
    DIRECTION INOUT ;
    USE POWER ;
    PORT
      LAYER M0 ;
        RECT -0.02 0.348 0.34 0.42 ;
    END
  END VDD
  PIN VSS
    DIRECTION INOUT ;
    USE GROUND ;
    PORT
      LAYER M0 ;
        RECT -0.02 -0.036 0.34 0.036 ;
    END
  END VSS
  OBS
    LAYER M0 ;
      RECT 0.188 0.204 0.252 0.228 ;
      RECT 0.108 0.156 0.172 0.18 ;
      RECT 0.068 0.108 0.132 0.132 ;
      RECT 0.268 0.06 0.292 0.084 ;
      RECT 0.028 0.3 0.292 0.324 ;
  END
END NAND3_X1

MACRO NAND4_X1
  CLASS CORE ;
  FOREIGN NAND4_X1 0 0 ;
  SIZE 0.48 BY 0.384 ;
  ORIGIN 0.0 0.0 ;
  SYMMETRY X Y ;
  PIN A1
    DIRECTION INPUT ;
    USE SIGNAL ;
    ANTENNAGATEAREA 0.00320 ;
    PORT
      LAYER M1 ;
        RECT 0.1 0.052 0.14 0.092 ;
    END
  END A1
  PIN A2
    DIRECTION INPUT ;
    USE SIGNAL ;
    ANTENNAGATEAREA 0.00320 ;
    PORT
      LAYER M1 ;
        RECT 0.18 0.148 0.22 0.188 ;
    END
  END A2
  PIN A3
    DIRECTION INPUT ;
    USE SIGNAL ;
    ANTENNAGATEAREA 0.00320 ;
    PORT
      LAYER M1 ;
        RECT 0.26 0.196 0.3 0.236 ;
    END
  END A3
  PIN A4
    DIRECTION INPUT ;
    USE SIGNAL ;
    ANTENNAGATEAREA 0.00320 ;
    PORT
      LAYER M1 ;
        RECT 0.34 0.1 0.38 0.14 ;
    END
  END A4
  PIN ZN
    DIRECTION OUTPUT ;
    USE SIGNAL ;
    ANTENNADIFFAREA 0.0192 ;
    PORT
      LAYER M1 ;
        RECT 0.02 0.052 0.06 0.332 ;
    END
  END ZN
  PIN VDD
    DIRECTION INOUT ;
    USE POWER ;
    PORT
      LAYER M0 ;
        RECT -0.02 0.348 0.5 0.42 ;
    END
  END VDD
  PIN VSS
    DIRECTION INOUT ;
    USE GROUND ;
    PORT
      LAYER M0 ;
        RECT -0.02 -0.036 0.5 0.036 ;
    END
  END VSS
  OBS
    LAYER M0 ;
      RECT 0.268 0.06 0.372 0.084 ;
      RECT 0.068 0.06 0.132 0.084 ;
      RECT 0.148 0.156 0.212 0.18 ;
      RECT 0.228 0.204 0.292 0.228 ;
      RECT 0.348 0.108 0.412 0.132 ;
      RECT 0.028 0.06 0.052 0.084 ;
      RECT 0.028 0.3 0.452 0.324 ;
  END
END NAND4_X1

MACRO NOR2_X1
  CLASS CORE ;
  FOREIGN NOR2_X1 0 0 ;
  SIZE 0.24 BY 0.384 ;
  ORIGIN 0.0 0.0 ;
  SYMMETRY X Y ;
  PIN A1
    DIRECTION INPUT ;
    USE SIGNAL ;
    ANTENNAGATEAREA 0.00320 ;
    PORT
      LAYER M1 ;
        RECT 0.18 0.196 0.22 0.236 ;
    END
  END A1
  PIN A2
    DIRECTION INPUT ;
    USE SIGNAL ;
    ANTENNAGATEAREA 0.00320 ;
    PORT
      LAYER M1 ;
        RECT 0.02 0.244 0.06 0.284 ;
    END
  END A2
  PIN ZN
    DIRECTION OUTPUT ;
    USE SIGNAL ;
    ANTENNADIFFAREA 0.0096 ;
    PORT
      LAYER M1 ;
        RECT 0.1 0.052 0.14 0.332 ;
    END
  END ZN
  PIN VDD
    DIRECTION INOUT ;
    USE POWER ;
    PORT
      LAYER M0 ;
        RECT -0.02 0.348 0.26 0.42 ;
    END
  END VDD
  PIN VSS
    DIRECTION INOUT ;
    USE GROUND ;
    PORT
      LAYER M0 ;
        RECT -0.02 -0.036 0.26 0.036 ;
    END
  END VSS
  OBS
    LAYER M0 ;
      RECT 0.148 0.204 0.212 0.228 ;
      RECT 0.028 0.252 0.092 0.276 ;
      RECT 0.108 0.06 0.132 0.084 ;
      RECT 0.108 0.3 0.212 0.324 ;
  END
END NOR2_X1

MACRO NOR2_X2
  CLASS CORE ;
  FOREIGN NOR2_X2 0 0 ;
  SIZE 0.4 BY 0.384 ;
  ORIGIN 0.0 0.0 ;
  SYMMETRY X Y ;
  PIN A1
    DIRECTION INPUT ;
    USE SIGNAL ;
    ANTENNAGATEAREA 0.00480 ;
    PORT
      LAYER M1 ;
        RECT 0.1 0.1 0.14 0.14 ;
    END
  END A1
  PIN A2
    DIRECTION INPUT ;
    USE SIGNAL ;
    ANTENNAGATEAREA 0.00640 ;
    PORT
      LAYER M1 ;
        RECT 0.1 0.148 0.14 0.236 ;
    END
  END A2
  PIN ZN
    DIRECTION OUTPUT ;
    USE SIGNAL ;
    ANTENNADIFFAREA 0.0144 ;
    PORT
      LAYER M1 ;
        RECT 0.18 0.052 0.22 0.332 ;
    END
  END ZN
  PIN VDD
    DIRECTION INOUT ;
    USE POWER ;
    PORT
      LAYER M0 ;
        RECT -0.02 0.348 0.42 0.42 ;
    END
  END VDD
  PIN VSS
    DIRECTION INOUT ;
    USE GROUND ;
    PORT
      LAYER M0 ;
        RECT -0.02 -0.036 0.42 0.036 ;
    END
  END VSS
  OBS
    LAYER M0 ;
      RECT 0.148 0.252 0.252 0.276 ;
      RECT 0.068 0.108 0.252 0.132 ;
      RECT 0.068 0.204 0.132 0.228 ;
      RECT 0.108 0.156 0.332 0.18 ;
      RECT 0.188 0.3 0.212 0.324 ;
      RECT 0.108 0.06 0.292 0.084 ;
  END
END NOR2_X2

MACRO NOR2_X4
  CLASS CORE ;
  FOREIGN NOR2_X4 0 0 ;
  SIZE 0.72 BY 0.384 ;
  ORIGIN 0.0 0.0 ;
  SYMMETRY X Y ;
  PIN A1
    DIRECTION INPUT ;
    USE SIGNAL ;
    ANTENNAGATEAREA 0.01280 ;
    PORT
      LAYER M1 ;
        RECT 0.1 0.148 0.14 0.188 ;
    END
  END A1
  PIN A2
    DIRECTION INPUT ;
    USE SIGNAL ;
    ANTENNAGATEAREA 0.01280 ;
    PORT
      LAYER M1 ;
        RECT 0.42 0.1 0.46 0.14 ;
    END
  END A2
  PIN ZN
    DIRECTION OUTPUT ;
    USE SIGNAL ;
    ANTENNADIFFAREA 0.0336 ;
    PORT
      LAYER M1 ;
        RECT 0.26 0.052 0.3 0.14 ;
        RECT 0.34 0.052 0.38 0.188 ;
        RECT 0.42 0.148 0.46 0.284 ;
        RECT 0.5 0.052 0.54 0.188 ;
        RECT 0.58 0.052 0.62 0.284 ;
    END
  END ZN
  PIN VDD
    DIRECTION INOUT ;
    USE POWER ;
    PORT
      LAYER M0 ;
        RECT -0.02 0.348 0.74 0.42 ;
    END
  END VDD
  PIN VSS
    DIRECTION INOUT ;
    USE GROUND ;
    PORT
      LAYER M0 ;
        RECT -0.02 -0.036 0.74 0.036 ;
    END
  END VSS
  OBS
    LAYER M0 ;
      RECT 0.028 0.3 0.692 0.324 ;
      RECT 0.068 0.156 0.332 0.18 ;
      RECT 0.388 0.108 0.652 0.132 ;
      RECT 0.268 0.108 0.372 0.132 ;
      RECT 0.028 0.06 0.292 0.084 ;
      RECT 0.348 0.156 0.612 0.18 ;
      RECT 0.348 0.06 0.372 0.084 ;
      RECT 0.508 0.06 0.532 0.084 ;
      RECT 0.588 0.06 0.692 0.084 ;
      RECT 0.588 0.252 0.612 0.276 ;
      RECT 0.428 0.252 0.452 0.276 ;
  END
END NOR2_X4

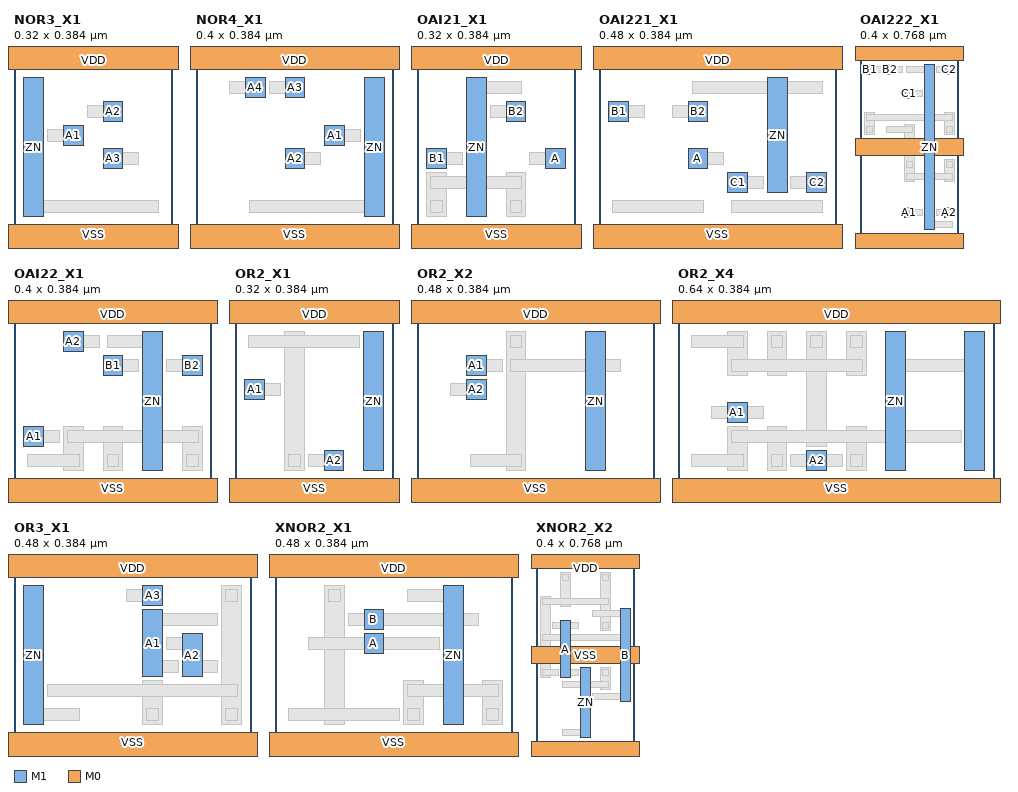
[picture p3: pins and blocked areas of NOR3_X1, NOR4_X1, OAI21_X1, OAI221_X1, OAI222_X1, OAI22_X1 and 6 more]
MACRO NOR3_X1
  CLASS CORE ;
  FOREIGN NOR3_X1 0 0 ;
  SIZE 0.32 BY 0.384 ;
  ORIGIN 0.0 0.0 ;
  SYMMETRY X Y ;
  PIN A1
    DIRECTION INPUT ;
    USE SIGNAL ;
    ANTENNAGATEAREA 0.00320 ;
    PORT
      LAYER M1 ;
        RECT 0.1 0.196 0.14 0.236 ;
    END
  END A1
  PIN A2
    DIRECTION INPUT ;
    USE SIGNAL ;
    ANTENNAGATEAREA 0.00320 ;
    PORT
      LAYER M1 ;
        RECT 0.18 0.244 0.22 0.284 ;
    END
  END A2
  PIN A3
    DIRECTION INPUT ;
    USE SIGNAL ;
    ANTENNAGATEAREA 0.00320 ;
    PORT
      LAYER M1 ;
        RECT 0.18 0.148 0.22 0.188 ;
    END
  END A3
  PIN ZN
    DIRECTION OUTPUT ;
    USE SIGNAL ;
    ANTENNADIFFAREA 0.0144 ;
    PORT
      LAYER M1 ;
        RECT 0.02 0.052 0.06 0.332 ;
    END
  END ZN
  PIN VDD
    DIRECTION INOUT ;
    USE POWER ;
    PORT
      LAYER M0 ;
        RECT -0.02 0.348 0.34 0.42 ;
    END
  END VDD
  PIN VSS
    DIRECTION INOUT ;
    USE GROUND ;
    PORT
      LAYER M0 ;
        RECT -0.02 -0.036 0.34 0.036 ;
    END
  END VSS
  OBS
    LAYER M0 ;
      RECT 0.068 0.204 0.132 0.228 ;
      RECT 0.148 0.252 0.212 0.276 ;
      RECT 0.188 0.156 0.252 0.18 ;
      RECT 0.028 0.3 0.052 0.324 ;
      RECT 0.028 0.06 0.292 0.084 ;
  END
END NOR3_X1

MACRO NOR4_X1
  CLASS CORE ;
  FOREIGN NOR4_X1 0 0 ;
  SIZE 0.4 BY 0.384 ;
  ORIGIN 0.0 0.0 ;
  SYMMETRY X Y ;
  PIN A1
    DIRECTION INPUT ;
    USE SIGNAL ;
    ANTENNAGATEAREA 0.00320 ;
    PORT
      LAYER M1 ;
        RECT 0.26 0.196 0.3 0.236 ;
    END
  END A1
  PIN A2
    DIRECTION INPUT ;
    USE SIGNAL ;
    ANTENNAGATEAREA 0.00320 ;
    PORT
      LAYER M1 ;
        RECT 0.18 0.148 0.22 0.188 ;
    END
  END A2
  PIN A3
    DIRECTION INPUT ;
    USE SIGNAL ;
    ANTENNAGATEAREA 0.00320 ;
    PORT
      LAYER M1 ;
        RECT 0.18 0.292 0.22 0.332 ;
    END
  END A3
  PIN A4
    DIRECTION INPUT ;
    USE SIGNAL ;
    ANTENNAGATEAREA 0.00320 ;
    PORT
      LAYER M1 ;
        RECT 0.1 0.292 0.14 0.332 ;
    END
  END A4
  PIN ZN
    DIRECTION OUTPUT ;
    USE SIGNAL ;
    ANTENNADIFFAREA 0.0144 ;
    PORT
      LAYER M1 ;
        RECT 0.34 0.052 0.38 0.332 ;
    END
  END ZN
  PIN VDD
    DIRECTION INOUT ;
    USE POWER ;
    PORT
      LAYER M0 ;
        RECT -0.02 0.348 0.42 0.42 ;
    END
  END VDD
  PIN VSS
    DIRECTION INOUT ;
    USE GROUND ;
    PORT
      LAYER M0 ;
        RECT -0.02 -0.036 0.42 0.036 ;
    END
  END VSS
  OBS
    LAYER M0 ;
      RECT 0.268 0.204 0.332 0.228 ;
      RECT 0.188 0.156 0.252 0.18 ;
      RECT 0.148 0.3 0.212 0.324 ;
      RECT 0.068 0.3 0.132 0.324 ;
      RECT 0.108 0.06 0.372 0.084 ;
      RECT 0.348 0.3 0.372 0.324 ;
  END
END NOR4_X1

MACRO OAI21_X1
  CLASS CORE ;
  FOREIGN OAI21_X1 0 0 ;
  SIZE 0.32 BY 0.384 ;
  ORIGIN 0.0 0.0 ;
  SYMMETRY X Y ;
  PIN A
    DIRECTION INPUT ;
    USE SIGNAL ;
    ANTENNAGATEAREA 0.00320 ;
    PORT
      LAYER M1 ;
        RECT 0.26 0.148 0.3 0.188 ;
    END
  END A
  PIN B1
    DIRECTION INPUT ;
    USE SIGNAL ;
    ANTENNAGATEAREA 0.00320 ;
    PORT
      LAYER M1 ;
        RECT 0.02 0.148 0.06 0.188 ;
    END
  END B1
  PIN B2
    DIRECTION INPUT ;
    USE SIGNAL ;
    ANTENNAGATEAREA 0.00320 ;
    PORT
      LAYER M1 ;
        RECT 0.18 0.244 0.22 0.284 ;
    END
  END B2
  PIN ZN
    DIRECTION OUTPUT ;
    USE SIGNAL ;
    ANTENNADIFFAREA 0.0096 ;
    PORT
      LAYER M1 ;
        RECT 0.1 0.052 0.14 0.332 ;
    END
  END ZN
  PIN VDD
    DIRECTION INOUT ;
    USE POWER ;
    PORT
      LAYER M0 ;
        RECT -0.02 0.348 0.34 0.42 ;
    END
  END VDD
  PIN VSS
    DIRECTION INOUT ;
    USE GROUND ;
    PORT
      LAYER M0 ;
        RECT -0.02 -0.036 0.34 0.036 ;
    END
  END VSS
  OBS
    LAYER M1 ;
      RECT 0.02 0.052 0.06 0.14 ;
      RECT 0.18 0.052 0.22 0.14 ;
    LAYER M0 ;
      RECT 0.028 0.108 0.212 0.132 ;
      RECT 0.028 0.06 0.052 0.084 ;
      RECT 0.188 0.06 0.212 0.084 ;
      RECT 0.228 0.156 0.292 0.18 ;
      RECT 0.028 0.156 0.092 0.18 ;
      RECT 0.148 0.252 0.212 0.276 ;
      RECT 0.108 0.06 0.132 0.084 ;
      RECT 0.108 0.3 0.212 0.324 ;
  END
END OAI21_X1

MACRO OAI221_X1
  CLASS CORE ;
  FOREIGN OAI221_X1 0 0 ;
  SIZE 0.48 BY 0.384 ;
  ORIGIN 0.0 0.0 ;
  SYMMETRY X Y ;
  PIN A
    DIRECTION INPUT ;
    USE SIGNAL ;
    ANTENNAGATEAREA 0.00320 ;
    PORT
      LAYER M1 ;
        RECT 0.18 0.148 0.22 0.188 ;
    END
  END A
  PIN B1
    DIRECTION INPUT ;
    USE SIGNAL ;
    ANTENNAGATEAREA 0.00320 ;
    PORT
      LAYER M1 ;
        RECT 0.02 0.244 0.06 0.284 ;
    END
  END B1
  PIN B2
    DIRECTION INPUT ;
    USE SIGNAL ;
    ANTENNAGATEAREA 0.00320 ;
    PORT
      LAYER M1 ;
        RECT 0.18 0.244 0.22 0.284 ;
    END
  END B2
  PIN C1
    DIRECTION INPUT ;
    USE SIGNAL ;
    ANTENNAGATEAREA 0.00320 ;
    PORT
      LAYER M1 ;
        RECT 0.26 0.1 0.3 0.14 ;
    END
  END C1
  PIN C2
    DIRECTION INPUT ;
    USE SIGNAL ;
    ANTENNAGATEAREA 0.00320 ;
    PORT
      LAYER M1 ;
        RECT 0.42 0.1 0.46 0.14 ;
    END
  END C2
  PIN ZN
    DIRECTION OUTPUT ;
    USE SIGNAL ;
    ANTENNADIFFAREA 0.0144 ;
    PORT
      LAYER M1 ;
        RECT 0.34 0.1 0.38 0.332 ;
    END
  END ZN
  PIN VDD
    DIRECTION INOUT ;
    USE POWER ;
    PORT
      LAYER M0 ;
        RECT -0.02 0.348 0.5 0.42 ;
    END
  END VDD
  PIN VSS
    DIRECTION INOUT ;
    USE GROUND ;
    PORT
      LAYER M0 ;
        RECT -0.02 -0.036 0.5 0.036 ;
    END
  END VSS
  OBS
    LAYER M0 ;
      RECT 0.268 0.06 0.452 0.084 ;
      RECT 0.028 0.06 0.212 0.084 ;
      RECT 0.188 0.156 0.252 0.18 ;
      RECT 0.028 0.252 0.092 0.276 ;
      RECT 0.148 0.252 0.212 0.276 ;
      RECT 0.268 0.108 0.332 0.132 ;
      RECT 0.388 0.108 0.452 0.132 ;
      RECT 0.348 0.108 0.372 0.132 ;
      RECT 0.188 0.3 0.452 0.324 ;
  END
END OAI221_X1

MACRO OAI222_X1
  CLASS CORE ;
  FOREIGN OAI222_X1 0 0 ;
  SIZE 0.4 BY 0.768 ;
  ORIGIN 0.0 0.0 ;
  SYMMETRY X Y ;
  PIN A1
    DIRECTION INPUT ;
    USE SIGNAL ;
    ANTENNAGATEAREA 0.00320 ;
    PORT
      LAYER M1 ;
        RECT 0.18 0.1 0.22 0.14 ;
    END
  END A1
  PIN A2
    DIRECTION INPUT ;
    USE SIGNAL ;
    ANTENNAGATEAREA 0.00320 ;
    PORT
      LAYER M1 ;
        RECT 0.34 0.1 0.38 0.14 ;
    END
  END A2
  PIN B1
    DIRECTION INPUT ;
    USE SIGNAL ;
    ANTENNAGATEAREA 0.00320 ;
    PORT
      LAYER M1 ;
        RECT 0.02 0.676 0.06 0.716 ;
    END
  END B1
  PIN B2
    DIRECTION INPUT ;
    USE SIGNAL ;
    ANTENNAGATEAREA 0.00320 ;
    PORT
      LAYER M1 ;
        RECT 0.1 0.676 0.14 0.716 ;
    END
  END B2
  PIN C1
    DIRECTION INPUT ;
    USE SIGNAL ;
    ANTENNAGATEAREA 0.00320 ;
    PORT
      LAYER M1 ;
        RECT 0.18 0.58 0.22 0.62 ;
    END
  END C1
  PIN C2
    DIRECTION INPUT ;
    USE SIGNAL ;
    ANTENNAGATEAREA 0.00320 ;
    PORT
      LAYER M1 ;
        RECT 0.34 0.676 0.38 0.716 ;
    END
  END C2
  PIN ZN
    DIRECTION OUTPUT ;
    USE SIGNAL ;
    ANTENNADIFFAREA 0.0144 ;
    PORT
      LAYER M1 ;
        RECT 0.26 0.052 0.3 0.716 ;
    END
  END ZN
  PIN VDD
    DIRECTION INOUT ;
    USE POWER ;
    PORT
      LAYER M0 ;
        RECT -0.02 -0.036 0.42 0.036 ;
        RECT -0.02 0.732 0.42 0.804 ;
    END
  END VDD
  PIN VSS
    DIRECTION INOUT ;
    USE GROUND ;
    PORT
      LAYER M0 ;
        RECT -0.02 0.348 0.42 0.42 ;
    END
  END VSS
  OBS
    LAYER M1 ;
      RECT 0.34 0.436 0.38 0.524 ;
      RECT 0.02 0.436 0.06 0.524 ;
      RECT 0.34 0.244 0.38 0.332 ;
      RECT 0.18 0.244 0.22 0.476 ;
    LAYER M0 ;
      RECT 0.348 0.444 0.372 0.468 ;
      RECT 0.028 0.444 0.052 0.468 ;
      RECT 0.348 0.3 0.372 0.324 ;
      RECT 0.188 0.3 0.212 0.324 ;
      RECT 0.028 0.492 0.372 0.516 ;
      RECT 0.188 0.252 0.372 0.276 ;
      RECT 0.108 0.444 0.212 0.468 ;
      RECT 0.188 0.108 0.252 0.132 ;
      RECT 0.308 0.108 0.372 0.132 ;
      RECT 0.028 0.684 0.092 0.708 ;
      RECT 0.108 0.684 0.172 0.708 ;
      RECT 0.188 0.588 0.252 0.612 ;
      RECT 0.308 0.684 0.372 0.708 ;
      RECT 0.268 0.3 0.292 0.324 ;
      RECT 0.188 0.684 0.292 0.708 ;
      RECT 0.268 0.06 0.372 0.084 ;
  END
END OAI222_X1

MACRO OAI22_X1
  CLASS CORE ;
  FOREIGN OAI22_X1 0 0 ;
  SIZE 0.4 BY 0.384 ;
  ORIGIN 0.0 0.0 ;
  SYMMETRY X Y ;
  PIN A1
    DIRECTION INPUT ;
    USE SIGNAL ;
    ANTENNAGATEAREA 0.00320 ;
    PORT
      LAYER M1 ;
        RECT 0.02 0.1 0.06 0.14 ;
    END
  END A1
  PIN A2
    DIRECTION INPUT ;
    USE SIGNAL ;
    ANTENNAGATEAREA 0.00320 ;
    PORT
      LAYER M1 ;
        RECT 0.1 0.292 0.14 0.332 ;
    END
  END A2
  PIN B1
    DIRECTION INPUT ;
    USE SIGNAL ;
    ANTENNAGATEAREA 0.00320 ;
    PORT
      LAYER M1 ;
        RECT 0.18 0.244 0.22 0.284 ;
    END
  END B1
  PIN B2
    DIRECTION INPUT ;
    USE SIGNAL ;
    ANTENNAGATEAREA 0.00320 ;
    PORT
      LAYER M1 ;
        RECT 0.34 0.244 0.38 0.284 ;
    END
  END B2
  PIN ZN
    DIRECTION OUTPUT ;
    USE SIGNAL ;
    ANTENNADIFFAREA 0.0096 ;
    PORT
      LAYER M1 ;
        RECT 0.26 0.052 0.3 0.332 ;
    END
  END ZN
  PIN VDD
    DIRECTION INOUT ;
    USE POWER ;
    PORT
      LAYER M0 ;
        RECT -0.02 0.348 0.42 0.42 ;
    END
  END VDD
  PIN VSS
    DIRECTION INOUT ;
    USE GROUND ;
    PORT
      LAYER M0 ;
        RECT -0.02 -0.036 0.42 0.036 ;
    END
  END VSS
  OBS
    LAYER M1 ;
      RECT 0.1 0.052 0.14 0.14 ;
      RECT 0.18 0.052 0.22 0.14 ;
      RECT 0.34 0.052 0.38 0.14 ;
    LAYER M0 ;
      RECT 0.108 0.108 0.372 0.132 ;
      RECT 0.028 0.06 0.132 0.084 ;
      RECT 0.188 0.06 0.212 0.084 ;
      RECT 0.348 0.06 0.372 0.084 ;
      RECT 0.028 0.108 0.092 0.132 ;
      RECT 0.108 0.3 0.172 0.324 ;
      RECT 0.188 0.252 0.252 0.276 ;
      RECT 0.308 0.252 0.372 0.276 ;
      RECT 0.268 0.06 0.292 0.084 ;
      RECT 0.188 0.3 0.292 0.324 ;
  END
END OAI22_X1

MACRO OR2_X1
  CLASS CORE ;
  FOREIGN OR2_X1 0 0 ;
  SIZE 0.32 BY 0.384 ;
  ORIGIN 0.0 0.0 ;
  SYMMETRY X Y ;
  PIN A1
    DIRECTION INPUT ;
    USE SIGNAL ;
    ANTENNAGATEAREA 0.00320 ;
    PORT
      LAYER M1 ;
        RECT 0.02 0.196 0.06 0.236 ;
    END
  END A1
  PIN A2
    DIRECTION INPUT ;
    USE SIGNAL ;
    ANTENNAGATEAREA 0.00320 ;
    PORT
      LAYER M1 ;
        RECT 0.18 0.052 0.22 0.092 ;
    END
  END A2
  PIN ZN
    DIRECTION OUTPUT ;
    USE SIGNAL ;
    ANTENNADIFFAREA 0.0096 ;
    PORT
      LAYER M1 ;
        RECT 0.26 0.052 0.3 0.332 ;
    END
  END ZN
  PIN VDD
    DIRECTION INOUT ;
    USE POWER ;
    PORT
      LAYER M0 ;
        RECT -0.02 0.348 0.34 0.42 ;
    END
  END VDD
  PIN VSS
    DIRECTION INOUT ;
    USE GROUND ;
    PORT
      LAYER M0 ;
        RECT -0.02 -0.036 0.34 0.036 ;
    END
  END VSS
  OBS
    LAYER M1 ;
      RECT 0.1 0.052 0.14 0.332 ;
    LAYER M0 ;
      RECT 0.028 0.3 0.252 0.324 ;
      RECT 0.108 0.06 0.132 0.084 ;
      RECT 0.028 0.204 0.092 0.228 ;
      RECT 0.148 0.06 0.212 0.084 ;
      RECT 0.268 0.06 0.292 0.084 ;
      RECT 0.268 0.3 0.292 0.324 ;
  END
END OR2_X1

MACRO OR2_X2
  CLASS CORE ;
  FOREIGN OR2_X2 0 0 ;
  SIZE 0.48 BY 0.384 ;
  ORIGIN 0.0 0.0 ;
  SYMMETRY X Y ;
  PIN A1
    DIRECTION INPUT ;
    USE SIGNAL ;
    ANTENNAGATEAREA 0.00320 ;
    PORT
      LAYER M1 ;
        RECT 0.1 0.244 0.14 0.284 ;
    END
  END A1
  PIN A2
    DIRECTION INPUT ;
    USE SIGNAL ;
    ANTENNAGATEAREA 0.00320 ;
    PORT
      LAYER M1 ;
        RECT 0.1 0.196 0.14 0.236 ;
    END
  END A2
  PIN ZN
    DIRECTION OUTPUT ;
    USE SIGNAL ;
    ANTENNADIFFAREA 0.0096 ;
    PORT
      LAYER M1 ;
        RECT 0.34 0.052 0.38 0.332 ;
    END
  END ZN
  PIN VDD
    DIRECTION INOUT ;
    USE POWER ;
    PORT
      LAYER M0 ;
        RECT -0.02 0.348 0.5 0.42 ;
    END
  END VDD
  PIN VSS
    DIRECTION INOUT ;
    USE GROUND ;
    PORT
      LAYER M0 ;
        RECT -0.02 -0.036 0.5 0.036 ;
    END
  END VSS
  OBS
    LAYER M1 ;
      RECT 0.18 0.052 0.22 0.332 ;
    LAYER M0 ;
      RECT 0.188 0.252 0.412 0.276 ;
      RECT 0.108 0.06 0.212 0.084 ;
      RECT 0.188 0.3 0.212 0.324 ;
      RECT 0.108 0.252 0.172 0.276 ;
      RECT 0.068 0.204 0.132 0.228 ;
      RECT 0.348 0.3 0.372 0.324 ;
      RECT 0.348 0.06 0.372 0.084 ;
  END
END OR2_X2

MACRO OR2_X4
  CLASS CORE ;
  FOREIGN OR2_X4 0 0 ;
  SIZE 0.64 BY 0.384 ;
  ORIGIN 0.0 0.0 ;
  SYMMETRY X Y ;
  PIN A1
    DIRECTION INPUT ;
    USE SIGNAL ;
    ANTENNAGATEAREA 0.00640 ;
    PORT
      LAYER M1 ;
        RECT 0.1 0.148 0.14 0.188 ;
    END
  END A1
  PIN A2
    DIRECTION INPUT ;
    USE SIGNAL ;
    ANTENNAGATEAREA 0.00640 ;
    PORT
      LAYER M1 ;
        RECT 0.26 0.052 0.3 0.092 ;
    END
  END A2
  PIN ZN
    DIRECTION OUTPUT ;
    USE SIGNAL ;
    ANTENNADIFFAREA 0.0192 ;
    PORT
      LAYER M1 ;
        RECT 0.42 0.052 0.46 0.332 ;
        RECT 0.58 0.052 0.62 0.332 ;
    END
  END ZN
  PIN VDD
    DIRECTION INOUT ;
    USE POWER ;
    PORT
      LAYER M0 ;
        RECT -0.02 0.348 0.66 0.42 ;
    END
  END VDD
  PIN VSS
    DIRECTION INOUT ;
    USE GROUND ;
    PORT
      LAYER M0 ;
        RECT -0.02 -0.036 0.66 0.036 ;
    END
  END VSS
  OBS
    LAYER M1 ;
      RECT 0.1 0.052 0.14 0.14 ;
      RECT 0.18 0.052 0.22 0.14 ;
      RECT 0.26 0.1 0.3 0.332 ;
      RECT 0.34 0.052 0.38 0.14 ;
      RECT 0.1 0.244 0.14 0.332 ;
      RECT 0.18 0.244 0.22 0.332 ;
      RECT 0.34 0.244 0.38 0.332 ;
    LAYER M0 ;
      RECT 0.108 0.108 0.572 0.132 ;
      RECT 0.028 0.06 0.132 0.084 ;
      RECT 0.028 0.3 0.132 0.324 ;
      RECT 0.108 0.252 0.372 0.276 ;
      RECT 0.268 0.3 0.292 0.324 ;
      RECT 0.188 0.06 0.212 0.084 ;
      RECT 0.348 0.06 0.372 0.084 ;
      RECT 0.188 0.3 0.212 0.324 ;
      RECT 0.348 0.3 0.372 0.324 ;
      RECT 0.068 0.156 0.172 0.18 ;
      RECT 0.228 0.06 0.332 0.084 ;
      RECT 0.428 0.252 0.612 0.276 ;
      RECT 0.428 0.06 0.452 0.084 ;
      RECT 0.428 0.3 0.452 0.324 ;
      RECT 0.588 0.06 0.612 0.084 ;
      RECT 0.588 0.3 0.612 0.324 ;
  END
END OR2_X4

MACRO OR3_X1
  CLASS CORE ;
  FOREIGN OR3_X1 0 0 ;
  SIZE 0.48 BY 0.384 ;
  ORIGIN 0.0 0.0 ;
  SYMMETRY X Y ;
  PIN A1
    DIRECTION INPUT ;
    USE SIGNAL ;
    ANTENNAGATEAREA 0.00320 ;
    PORT
      LAYER M1 ;
        RECT 0.26 0.148 0.3 0.284 ;
    END
  END A1
  PIN A2
    DIRECTION INPUT ;
    USE SIGNAL ;
    ANTENNAGATEAREA 0.00320 ;
    PORT
      LAYER M1 ;
        RECT 0.34 0.148 0.38 0.236 ;
    END
  END A2
  PIN A3
    DIRECTION INPUT ;
    USE SIGNAL ;
    ANTENNAGATEAREA 0.00320 ;
    PORT
      LAYER M1 ;
        RECT 0.26 0.292 0.3 0.332 ;
    END
  END A3
  PIN ZN
    DIRECTION OUTPUT ;
    USE SIGNAL ;
    ANTENNADIFFAREA 0.0096 ;
    PORT
      LAYER M1 ;
        RECT 0.02 0.052 0.06 0.332 ;
    END
  END ZN
  PIN VDD
    DIRECTION INOUT ;
    USE POWER ;
    PORT
      LAYER M0 ;
        RECT -0.02 0.348 0.5 0.42 ;
    END
  END VDD
  PIN VSS
    DIRECTION INOUT ;
    USE GROUND ;
    PORT
      LAYER M0 ;
        RECT -0.02 -0.036 0.5 0.036 ;
    END
  END VSS
  OBS
    LAYER M1 ;
      RECT 0.26 0.052 0.3 0.14 ;
      RECT 0.42 0.052 0.46 0.332 ;
    LAYER M0 ;
      RECT 0.068 0.108 0.452 0.132 ;
      RECT 0.428 0.3 0.452 0.324 ;
      RECT 0.268 0.06 0.292 0.084 ;
      RECT 0.428 0.06 0.452 0.084 ;
      RECT 0.268 0.156 0.332 0.18 ;
      RECT 0.268 0.252 0.412 0.276 ;
      RECT 0.348 0.156 0.412 0.18 ;
      RECT 0.308 0.204 0.372 0.228 ;
      RECT 0.228 0.3 0.292 0.324 ;
      RECT 0.028 0.06 0.132 0.084 ;
      RECT 0.028 0.3 0.052 0.324 ;
  END
END OR3_X1

MACRO XNOR2_X1
  CLASS CORE ;
  FOREIGN XNOR2_X1 0 0 ;
  SIZE 0.48 BY 0.384 ;
  ORIGIN 0.0 0.0 ;
  SYMMETRY X Y ;
  PIN A
    DIRECTION INPUT ;
    USE SIGNAL ;
    ANTENNAGATEAREA 0.00640 ;
    PORT
      LAYER M1 ;
        RECT 0.18 0.196 0.22 0.236 ;
    END
  END A
  PIN B
    DIRECTION INPUT ;
    USE SIGNAL ;
    ANTENNAGATEAREA 0.00640 ;
    PORT
      LAYER M1 ;
        RECT 0.18 0.244 0.22 0.284 ;
    END
  END B
  PIN ZN
    DIRECTION OUTPUT ;
    USE SIGNAL ;
    ANTENNADIFFAREA 0.0096 ;
    PORT
      LAYER M1 ;
        RECT 0.34 0.052 0.38 0.332 ;
    END
  END ZN
  PIN VDD
    DIRECTION INOUT ;
    USE POWER ;
    PORT
      LAYER M0 ;
        RECT -0.02 0.348 0.5 0.42 ;
    END
  END VDD
  PIN VSS
    DIRECTION INOUT ;
    USE GROUND ;
    PORT
      LAYER M0 ;
        RECT -0.02 -0.036 0.5 0.036 ;
    END
  END VSS
  OBS
    LAYER M1 ;
      RECT 0.1 0.052 0.14 0.332 ;
      RECT 0.26 0.052 0.3 0.14 ;
      RECT 0.42 0.052 0.46 0.14 ;
    LAYER M0 ;
      RECT 0.028 0.06 0.252 0.084 ;
      RECT 0.268 0.108 0.452 0.132 ;
      RECT 0.108 0.3 0.132 0.324 ;
      RECT 0.268 0.06 0.292 0.084 ;
      RECT 0.428 0.06 0.452 0.084 ;
      RECT 0.068 0.204 0.332 0.228 ;
      RECT 0.148 0.252 0.412 0.276 ;
      RECT 0.348 0.06 0.372 0.084 ;
      RECT 0.268 0.3 0.372 0.324 ;
  END
END XNOR2_X1

MACRO XNOR2_X2
  CLASS CORE ;
  FOREIGN XNOR2_X2 0 0 ;
  SIZE 0.4 BY 0.768 ;
  ORIGIN 0.0 0.0 ;
  SYMMETRY X Y ;
  PIN A
    DIRECTION INPUT ;
    USE SIGNAL ;
    ANTENNAGATEAREA 0.00960 ;
    PORT
      LAYER M1 ;
        RECT 0.1 0.292 0.14 0.524 ;
    END
  END A
  PIN B
    DIRECTION INPUT ;
    USE SIGNAL ;
    ANTENNAGATEAREA 0.00960 ;
    PORT
      LAYER M1 ;
        RECT 0.34 0.196 0.38 0.572 ;
    END
  END B
  PIN ZN
    DIRECTION OUTPUT ;
    USE SIGNAL ;
    ANTENNADIFFAREA 0.0096 ;
    PORT
      LAYER M1 ;
        RECT 0.18 0.052 0.22 0.332 ;
    END
  END ZN
  PIN VDD
    DIRECTION INOUT ;
    USE POWER ;
    PORT
      LAYER M0 ;
        RECT -0.02 0.732 0.42 0.804 ;
        RECT -0.02 -0.036 0.42 0.036 ;
    END
  END VDD
  PIN VSS
    DIRECTION INOUT ;
    USE GROUND ;
    PORT
      LAYER M0 ;
        RECT -0.02 0.348 0.42 0.42 ;
    END
  END VSS
  OBS
    LAYER M1 ;
      RECT 0.02 0.292 0.06 0.62 ;
      RECT 0.1 0.58 0.14 0.716 ;
      RECT 0.26 0.484 0.3 0.716 ;
      RECT 0.26 0.244 0.3 0.332 ;
    LAYER M0 ;
      RECT 0.028 0.444 0.372 0.468 ;
      RECT 0.028 0.588 0.292 0.612 ;
      RECT 0.028 0.3 0.092 0.324 ;
      RECT 0.108 0.252 0.292 0.276 ;
      RECT 0.108 0.684 0.132 0.708 ;
      RECT 0.268 0.684 0.292 0.708 ;
      RECT 0.268 0.492 0.292 0.516 ;
      RECT 0.268 0.3 0.292 0.324 ;
      RECT 0.068 0.492 0.172 0.516 ;
      RECT 0.108 0.3 0.172 0.324 ;
      RECT 0.228 0.204 0.372 0.228 ;
      RECT 0.228 0.54 0.372 0.564 ;
      RECT 0.108 0.06 0.212 0.084 ;
      RECT 0.188 0.3 0.212 0.324 ;
  END
END XNOR2_X2

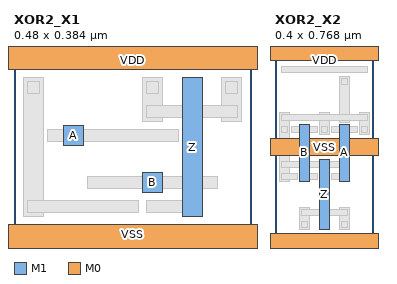
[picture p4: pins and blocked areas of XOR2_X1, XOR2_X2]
MACRO XOR2_X1
  CLASS CORE ;
  FOREIGN XOR2_X1 0 0 ;
  SIZE 0.48 BY 0.384 ;
  ORIGIN 0.0 0.0 ;
  SYMMETRY X Y ;
  PIN A
    DIRECTION INPUT ;
    USE SIGNAL ;
    ANTENNAGATEAREA 0.00640 ;
    PORT
      LAYER M1 ;
        RECT 0.1 0.196 0.14 0.236 ;
    END
  END A
  PIN B
    DIRECTION INPUT ;
    USE SIGNAL ;
    ANTENNAGATEAREA 0.00640 ;
    PORT
      LAYER M1 ;
        RECT 0.26 0.1 0.3 0.14 ;
    END
  END B
  PIN Z
    DIRECTION OUTPUT ;
    USE SIGNAL ;
    ANTENNADIFFAREA 0.0096 ;
    PORT
      LAYER M1 ;
        RECT 0.34 0.052 0.38 0.332 ;
    END
  END Z
  PIN VDD
    DIRECTION INOUT ;
    USE POWER ;
    PORT
      LAYER M0 ;
        RECT -0.02 0.348 0.5 0.42 ;
    END
  END VDD
  PIN VSS
    DIRECTION INOUT ;
    USE GROUND ;
    PORT
      LAYER M0 ;
        RECT -0.02 -0.036 0.5 0.036 ;
    END
  END VSS
  OBS
    LAYER M1 ;
      RECT 0.26 0.244 0.3 0.332 ;
      RECT 0.42 0.244 0.46 0.332 ;
      RECT 0.02 0.052 0.06 0.332 ;
    LAYER M0 ;
      RECT 0.268 0.252 0.452 0.276 ;
      RECT 0.028 0.06 0.252 0.084 ;
      RECT 0.268 0.3 0.292 0.324 ;
      RECT 0.428 0.3 0.452 0.324 ;
      RECT 0.028 0.3 0.052 0.324 ;
      RECT 0.068 0.204 0.332 0.228 ;
      RECT 0.148 0.108 0.412 0.132 ;
      RECT 0.348 0.3 0.372 0.324 ;
      RECT 0.268 0.06 0.372 0.084 ;
  END
END XOR2_X1

MACRO XOR2_X2
  CLASS CORE ;
  FOREIGN XOR2_X2 0 0 ;
  SIZE 0.4 BY 0.768 ;
  ORIGIN 0.0 0.0 ;
  SYMMETRY X Y ;
  PIN A
    DIRECTION INPUT ;
    USE SIGNAL ;
    ANTENNAGATEAREA 0.00960 ;
    PORT
      LAYER M1 ;
        RECT 0.26 0.244 0.3 0.476 ;
    END
  END A
  PIN B
    DIRECTION INPUT ;
    USE SIGNAL ;
    ANTENNAGATEAREA 0.00960 ;
    PORT
      LAYER M1 ;
        RECT 0.1 0.244 0.14 0.476 ;
    END
  END B
  PIN Z
    DIRECTION OUTPUT ;
    USE SIGNAL ;
    ANTENNADIFFAREA 0.0144 ;
    PORT
      LAYER M1 ;
        RECT 0.18 0.052 0.22 0.332 ;
    END
  END Z
  PIN VDD
    DIRECTION INOUT ;
    USE POWER ;
    PORT
      LAYER M0 ;
        RECT -0.02 0.732 0.42 0.804 ;
        RECT -0.02 -0.036 0.42 0.036 ;
    END
  END VDD
  PIN VSS
    DIRECTION INOUT ;
    USE GROUND ;
    PORT
      LAYER M0 ;
        RECT -0.02 0.348 0.42 0.42 ;
    END
  END VSS
  OBS
    LAYER M1 ;
      RECT 0.1 0.052 0.14 0.14 ;
      RECT 0.26 0.052 0.3 0.14 ;
      RECT 0.02 0.244 0.06 0.524 ;
      RECT 0.18 0.436 0.22 0.524 ;
      RECT 0.26 0.484 0.3 0.668 ;
      RECT 0.34 0.436 0.38 0.524 ;
    LAYER M0 ;
      RECT 0.028 0.684 0.372 0.708 ;
      RECT 0.108 0.108 0.292 0.132 ;
      RECT 0.028 0.492 0.372 0.516 ;
      RECT 0.028 0.252 0.092 0.276 ;
      RECT 0.108 0.06 0.132 0.084 ;
      RECT 0.268 0.06 0.292 0.084 ;
      RECT 0.268 0.636 0.292 0.66 ;
      RECT 0.028 0.444 0.052 0.468 ;
      RECT 0.188 0.444 0.212 0.468 ;
      RECT 0.348 0.444 0.372 0.468 ;
      RECT 0.228 0.252 0.292 0.276 ;
      RECT 0.228 0.444 0.332 0.468 ;
      RECT 0.068 0.444 0.172 0.468 ;
      RECT 0.108 0.252 0.172 0.276 ;
      RECT 0.028 0.3 0.292 0.324 ;
      RECT 0.188 0.06 0.212 0.084 ;
  END
END XOR2_X2

END LIBRARY
